VERSION 5.7 ;
BUSBITCHARS "[]" ;
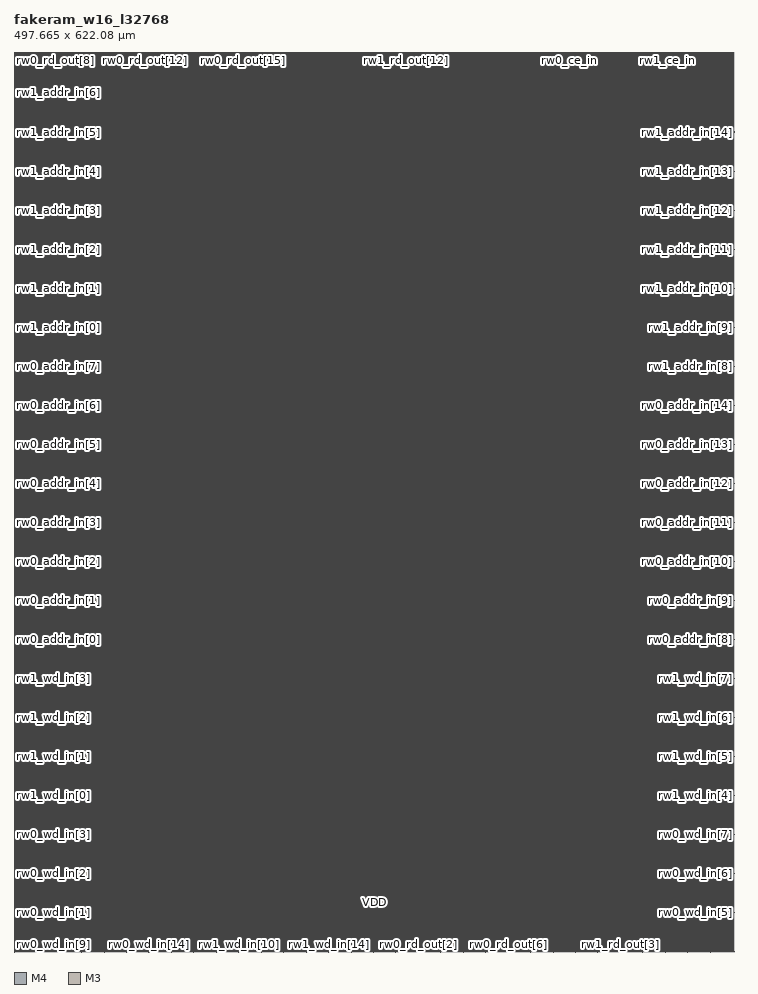
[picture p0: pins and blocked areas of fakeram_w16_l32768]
MACRO fakeram_w16_l32768
  FOREIGN fakeram_w16_l32768 0 0 ;
  SYMMETRY X Y R90 ;
  SIZE 497.665 BY 622.080 ;
  CLASS BLOCK ;
  PIN rw0_wd_in[0]
    DIRECTION INPUT ;
    USE SIGNAL ;
    SHAPE ABUTMENT ;
    PORT
      LAYER M4 ;
      RECT 0.000 0.276 0.072 0.300 ;
    END
  END rw0_wd_in[0]
  PIN rw0_wd_in[1]
    DIRECTION INPUT ;
    USE SIGNAL ;
    SHAPE ABUTMENT ;
    PORT
      LAYER M4 ;
      RECT 0.000 27.252 0.072 27.276 ;
    END
  END rw0_wd_in[1]
  PIN rw0_wd_in[2]
    DIRECTION INPUT ;
    USE SIGNAL ;
    SHAPE ABUTMENT ;
    PORT
      LAYER M4 ;
      RECT 0.000 54.228 0.072 54.252 ;
    END
  END rw0_wd_in[2]
  PIN rw0_wd_in[3]
    DIRECTION INPUT ;
    USE SIGNAL ;
    SHAPE ABUTMENT ;
    PORT
      LAYER M4 ;
      RECT 0.000 81.204 0.072 81.228 ;
    END
  END rw0_wd_in[3]
  PIN rw0_wd_in[4]
    DIRECTION INPUT ;
    USE SIGNAL ;
    SHAPE ABUTMENT ;
    PORT
      LAYER M4 ;
      RECT 497.593 0.276 497.665 0.300 ;
    END
  END rw0_wd_in[4]
  PIN rw0_wd_in[5]
    DIRECTION INPUT ;
    USE SIGNAL ;
    SHAPE ABUTMENT ;
    PORT
      LAYER M4 ;
      RECT 497.593 27.252 497.665 27.276 ;
    END
  END rw0_wd_in[5]
  PIN rw0_wd_in[6]
    DIRECTION INPUT ;
    USE SIGNAL ;
    SHAPE ABUTMENT ;
    PORT
      LAYER M4 ;
      RECT 497.593 54.228 497.665 54.252 ;
    END
  END rw0_wd_in[6]
  PIN rw0_wd_in[7]
    DIRECTION INPUT ;
    USE SIGNAL ;
    SHAPE ABUTMENT ;
    PORT
      LAYER M4 ;
      RECT 497.593 81.204 497.665 81.228 ;
    END
  END rw0_wd_in[7]
  PIN rw0_wd_in[8]
    DIRECTION INPUT ;
    USE SIGNAL ;
    SHAPE ABUTMENT ;
    PORT
      LAYER M3 ;
      RECT 0.207 0.000 0.225 0.054 ;
    END
  END rw0_wd_in[8]
  PIN rw0_wd_in[9]
    DIRECTION INPUT ;
    USE SIGNAL ;
    SHAPE ABUTMENT ;
    PORT
      LAYER M3 ;
      RECT 15.723 0.000 15.741 0.054 ;
    END
  END rw0_wd_in[9]
  PIN rw0_wd_in[10]
    DIRECTION INPUT ;
    USE SIGNAL ;
    SHAPE ABUTMENT ;
    PORT
      LAYER M3 ;
      RECT 31.239 0.000 31.257 0.054 ;
    END
  END rw0_wd_in[10]
  PIN rw0_wd_in[11]
    DIRECTION INPUT ;
    USE SIGNAL ;
    SHAPE ABUTMENT ;
    PORT
      LAYER M3 ;
      RECT 46.755 0.000 46.773 0.054 ;
    END
  END rw0_wd_in[11]
  PIN rw0_wd_in[12]
    DIRECTION INPUT ;
    USE SIGNAL ;
    SHAPE ABUTMENT ;
    PORT
      LAYER M3 ;
      RECT 62.271 0.000 62.289 0.054 ;
    END
  END rw0_wd_in[12]
  PIN rw0_wd_in[13]
    DIRECTION INPUT ;
    USE SIGNAL ;
    SHAPE ABUTMENT ;
    PORT
      LAYER M3 ;
      RECT 77.787 0.000 77.805 0.054 ;
    END
  END rw0_wd_in[13]
  PIN rw0_wd_in[14]
    DIRECTION INPUT ;
    USE SIGNAL ;
    SHAPE ABUTMENT ;
    PORT
      LAYER M3 ;
      RECT 93.303 0.000 93.321 0.054 ;
    END
  END rw0_wd_in[14]
  PIN rw0_wd_in[15]
    DIRECTION INPUT ;
    USE SIGNAL ;
    SHAPE ABUTMENT ;
    PORT
      LAYER M3 ;
      RECT 108.819 0.000 108.837 0.054 ;
    END
  END rw0_wd_in[15]
  PIN rw1_wd_in[0]
    DIRECTION INPUT ;
    USE SIGNAL ;
    SHAPE ABUTMENT ;
    PORT
      LAYER M4 ;
      RECT 0.000 108.180 0.072 108.204 ;
    END
  END rw1_wd_in[0]
  PIN rw1_wd_in[1]
    DIRECTION INPUT ;
    USE SIGNAL ;
    SHAPE ABUTMENT ;
    PORT
      LAYER M4 ;
      RECT 0.000 135.156 0.072 135.180 ;
    END
  END rw1_wd_in[1]
  PIN rw1_wd_in[2]
    DIRECTION INPUT ;
    USE SIGNAL ;
    SHAPE ABUTMENT ;
    PORT
      LAYER M4 ;
      RECT 0.000 162.132 0.072 162.156 ;
    END
  END rw1_wd_in[2]
  PIN rw1_wd_in[3]
    DIRECTION INPUT ;
    USE SIGNAL ;
    SHAPE ABUTMENT ;
    PORT
      LAYER M4 ;
      RECT 0.000 189.108 0.072 189.132 ;
    END
  END rw1_wd_in[3]
  PIN rw1_wd_in[4]
    DIRECTION INPUT ;
    USE SIGNAL ;
    SHAPE ABUTMENT ;
    PORT
      LAYER M4 ;
      RECT 497.593 108.180 497.665 108.204 ;
    END
  END rw1_wd_in[4]
  PIN rw1_wd_in[5]
    DIRECTION INPUT ;
    USE SIGNAL ;
    SHAPE ABUTMENT ;
    PORT
      LAYER M4 ;
      RECT 497.593 135.156 497.665 135.180 ;
    END
  END rw1_wd_in[5]
  PIN rw1_wd_in[6]
    DIRECTION INPUT ;
    USE SIGNAL ;
    SHAPE ABUTMENT ;
    PORT
      LAYER M4 ;
      RECT 497.593 162.132 497.665 162.156 ;
    END
  END rw1_wd_in[6]
  PIN rw1_wd_in[7]
    DIRECTION INPUT ;
    USE SIGNAL ;
    SHAPE ABUTMENT ;
    PORT
      LAYER M4 ;
      RECT 497.593 189.108 497.665 189.132 ;
    END
  END rw1_wd_in[7]
  PIN rw1_wd_in[8]
    DIRECTION INPUT ;
    USE SIGNAL ;
    SHAPE ABUTMENT ;
    PORT
      LAYER M3 ;
      RECT 124.335 0.000 124.353 0.054 ;
    END
  END rw1_wd_in[8]
  PIN rw1_wd_in[9]
    DIRECTION INPUT ;
    USE SIGNAL ;
    SHAPE ABUTMENT ;
    PORT
      LAYER M3 ;
      RECT 139.851 0.000 139.869 0.054 ;
    END
  END rw1_wd_in[9]
  PIN rw1_wd_in[10]
    DIRECTION INPUT ;
    USE SIGNAL ;
    SHAPE ABUTMENT ;
    PORT
      LAYER M3 ;
      RECT 155.367 0.000 155.385 0.054 ;
    END
  END rw1_wd_in[10]
  PIN rw1_wd_in[11]
    DIRECTION INPUT ;
    USE SIGNAL ;
    SHAPE ABUTMENT ;
    PORT
      LAYER M3 ;
      RECT 170.883 0.000 170.901 0.054 ;
    END
  END rw1_wd_in[11]
  PIN rw1_wd_in[12]
    DIRECTION INPUT ;
    USE SIGNAL ;
    SHAPE ABUTMENT ;
    PORT
      LAYER M3 ;
      RECT 186.399 0.000 186.417 0.054 ;
    END
  END rw1_wd_in[12]
  PIN rw1_wd_in[13]
    DIRECTION INPUT ;
    USE SIGNAL ;
    SHAPE ABUTMENT ;
    PORT
      LAYER M3 ;
      RECT 201.915 0.000 201.933 0.054 ;
    END
  END rw1_wd_in[13]
  PIN rw1_wd_in[14]
    DIRECTION INPUT ;
    USE SIGNAL ;
    SHAPE ABUTMENT ;
    PORT
      LAYER M3 ;
      RECT 217.431 0.000 217.449 0.054 ;
    END
  END rw1_wd_in[14]
  PIN rw1_wd_in[15]
    DIRECTION INPUT ;
    USE SIGNAL ;
    SHAPE ABUTMENT ;
    PORT
      LAYER M3 ;
      RECT 232.947 0.000 232.965 0.054 ;
    END
  END rw1_wd_in[15]
  PIN rw0_rd_out[0]
    DIRECTION OUTPUT ;
    USE SIGNAL ;
    SHAPE ABUTMENT ;
    PORT
      LAYER M3 ;
      RECT 248.463 0.000 248.481 0.054 ;
    END
  END rw0_rd_out[0]
  PIN rw0_rd_out[1]
    DIRECTION OUTPUT ;
    USE SIGNAL ;
    SHAPE ABUTMENT ;
    PORT
      LAYER M3 ;
      RECT 263.979 0.000 263.997 0.054 ;
    END
  END rw0_rd_out[1]
  PIN rw0_rd_out[2]
    DIRECTION OUTPUT ;
    USE SIGNAL ;
    SHAPE ABUTMENT ;
    PORT
      LAYER M3 ;
      RECT 279.495 0.000 279.513 0.054 ;
    END
  END rw0_rd_out[2]
  PIN rw0_rd_out[3]
    DIRECTION OUTPUT ;
    USE SIGNAL ;
    SHAPE ABUTMENT ;
    PORT
      LAYER M3 ;
      RECT 295.011 0.000 295.029 0.054 ;
    END
  END rw0_rd_out[3]
  PIN rw0_rd_out[4]
    DIRECTION OUTPUT ;
    USE SIGNAL ;
    SHAPE ABUTMENT ;
    PORT
      LAYER M3 ;
      RECT 310.527 0.000 310.545 0.054 ;
    END
  END rw0_rd_out[4]
  PIN rw0_rd_out[5]
    DIRECTION OUTPUT ;
    USE SIGNAL ;
    SHAPE ABUTMENT ;
    PORT
      LAYER M3 ;
      RECT 326.043 0.000 326.061 0.054 ;
    END
  END rw0_rd_out[5]
  PIN rw0_rd_out[6]
    DIRECTION OUTPUT ;
    USE SIGNAL ;
    SHAPE ABUTMENT ;
    PORT
      LAYER M3 ;
      RECT 341.559 0.000 341.577 0.054 ;
    END
  END rw0_rd_out[6]
  PIN rw0_rd_out[7]
    DIRECTION OUTPUT ;
    USE SIGNAL ;
    SHAPE ABUTMENT ;
    PORT
      LAYER M3 ;
      RECT 357.075 0.000 357.093 0.054 ;
    END
  END rw0_rd_out[7]
  PIN rw0_rd_out[8]
    DIRECTION OUTPUT ;
    USE SIGNAL ;
    SHAPE ABUTMENT ;
    PORT
      LAYER M3 ;
      RECT 0.207 622.026 0.225 622.080 ;
    END
  END rw0_rd_out[8]
  PIN rw0_rd_out[9]
    DIRECTION OUTPUT ;
    USE SIGNAL ;
    SHAPE ABUTMENT ;
    PORT
      LAYER M3 ;
      RECT 22.779 622.026 22.797 622.080 ;
    END
  END rw0_rd_out[9]
  PIN rw0_rd_out[10]
    DIRECTION OUTPUT ;
    USE SIGNAL ;
    SHAPE ABUTMENT ;
    PORT
      LAYER M3 ;
      RECT 45.351 622.026 45.369 622.080 ;
    END
  END rw0_rd_out[10]
  PIN rw0_rd_out[11]
    DIRECTION OUTPUT ;
    USE SIGNAL ;
    SHAPE ABUTMENT ;
    PORT
      LAYER M3 ;
      RECT 67.923 622.026 67.941 622.080 ;
    END
  END rw0_rd_out[11]
  PIN rw0_rd_out[12]
    DIRECTION OUTPUT ;
    USE SIGNAL ;
    SHAPE ABUTMENT ;
    PORT
      LAYER M3 ;
      RECT 90.495 622.026 90.513 622.080 ;
    END
  END rw0_rd_out[12]
  PIN rw0_rd_out[13]
    DIRECTION OUTPUT ;
    USE SIGNAL ;
    SHAPE ABUTMENT ;
    PORT
      LAYER M3 ;
      RECT 113.067 622.026 113.085 622.080 ;
    END
  END rw0_rd_out[13]
  PIN rw0_rd_out[14]
    DIRECTION OUTPUT ;
    USE SIGNAL ;
    SHAPE ABUTMENT ;
    PORT
      LAYER M3 ;
      RECT 135.639 622.026 135.657 622.080 ;
    END
  END rw0_rd_out[14]
  PIN rw0_rd_out[15]
    DIRECTION OUTPUT ;
    USE SIGNAL ;
    SHAPE ABUTMENT ;
    PORT
      LAYER M3 ;
      RECT 158.211 622.026 158.229 622.080 ;
    END
  END rw0_rd_out[15]
  PIN rw1_rd_out[0]
    DIRECTION OUTPUT ;
    USE SIGNAL ;
    SHAPE ABUTMENT ;
    PORT
      LAYER M3 ;
      RECT 372.591 0.000 372.609 0.054 ;
    END
  END rw1_rd_out[0]
  PIN rw1_rd_out[1]
    DIRECTION OUTPUT ;
    USE SIGNAL ;
    SHAPE ABUTMENT ;
    PORT
      LAYER M3 ;
      RECT 388.107 0.000 388.125 0.054 ;
    END
  END rw1_rd_out[1]
  PIN rw1_rd_out[2]
    DIRECTION OUTPUT ;
    USE SIGNAL ;
    SHAPE ABUTMENT ;
    PORT
      LAYER M3 ;
      RECT 403.623 0.000 403.641 0.054 ;
    END
  END rw1_rd_out[2]
  PIN rw1_rd_out[3]
    DIRECTION OUTPUT ;
    USE SIGNAL ;
    SHAPE ABUTMENT ;
    PORT
      LAYER M3 ;
      RECT 419.139 0.000 419.157 0.054 ;
    END
  END rw1_rd_out[3]
  PIN rw1_rd_out[4]
    DIRECTION OUTPUT ;
    USE SIGNAL ;
    SHAPE ABUTMENT ;
    PORT
      LAYER M3 ;
      RECT 434.655 0.000 434.673 0.054 ;
    END
  END rw1_rd_out[4]
  PIN rw1_rd_out[5]
    DIRECTION OUTPUT ;
    USE SIGNAL ;
    SHAPE ABUTMENT ;
    PORT
      LAYER M3 ;
      RECT 450.171 0.000 450.189 0.054 ;
    END
  END rw1_rd_out[5]
  PIN rw1_rd_out[6]
    DIRECTION OUTPUT ;
    USE SIGNAL ;
    SHAPE ABUTMENT ;
    PORT
      LAYER M3 ;
      RECT 465.687 0.000 465.705 0.054 ;
    END
  END rw1_rd_out[6]
  PIN rw1_rd_out[7]
    DIRECTION OUTPUT ;
    USE SIGNAL ;
    SHAPE ABUTMENT ;
    PORT
      LAYER M3 ;
      RECT 481.203 0.000 481.221 0.054 ;
    END
  END rw1_rd_out[7]
  PIN rw1_rd_out[8]
    DIRECTION OUTPUT ;
    USE SIGNAL ;
    SHAPE ABUTMENT ;
    PORT
      LAYER M3 ;
      RECT 180.783 622.026 180.801 622.080 ;
    END
  END rw1_rd_out[8]
  PIN rw1_rd_out[9]
    DIRECTION OUTPUT ;
    USE SIGNAL ;
    SHAPE ABUTMENT ;
    PORT
      LAYER M3 ;
      RECT 203.355 622.026 203.373 622.080 ;
    END
  END rw1_rd_out[9]
  PIN rw1_rd_out[10]
    DIRECTION OUTPUT ;
    USE SIGNAL ;
    SHAPE ABUTMENT ;
    PORT
      LAYER M3 ;
      RECT 225.927 622.026 225.945 622.080 ;
    END
  END rw1_rd_out[10]
  PIN rw1_rd_out[11]
    DIRECTION OUTPUT ;
    USE SIGNAL ;
    SHAPE ABUTMENT ;
    PORT
      LAYER M3 ;
      RECT 248.499 622.026 248.517 622.080 ;
    END
  END rw1_rd_out[11]
  PIN rw1_rd_out[12]
    DIRECTION OUTPUT ;
    USE SIGNAL ;
    SHAPE ABUTMENT ;
    PORT
      LAYER M3 ;
      RECT 271.071 622.026 271.089 622.080 ;
    END
  END rw1_rd_out[12]
  PIN rw1_rd_out[13]
    DIRECTION OUTPUT ;
    USE SIGNAL ;
    SHAPE ABUTMENT ;
    PORT
      LAYER M3 ;
      RECT 293.643 622.026 293.661 622.080 ;
    END
  END rw1_rd_out[13]
  PIN rw1_rd_out[14]
    DIRECTION OUTPUT ;
    USE SIGNAL ;
    SHAPE ABUTMENT ;
    PORT
      LAYER M3 ;
      RECT 316.215 622.026 316.233 622.080 ;
    END
  END rw1_rd_out[14]
  PIN rw1_rd_out[15]
    DIRECTION OUTPUT ;
    USE SIGNAL ;
    SHAPE ABUTMENT ;
    PORT
      LAYER M3 ;
      RECT 338.787 622.026 338.805 622.080 ;
    END
  END rw1_rd_out[15]
  PIN rw0_addr_in[0]
    DIRECTION INPUT ;
    USE SIGNAL ;
    SHAPE ABUTMENT ;
    PORT
      LAYER M4 ;
      RECT 0.000 216.084 0.072 216.108 ;
    END
  END rw0_addr_in[0]
  PIN rw0_addr_in[1]
    DIRECTION INPUT ;
    USE SIGNAL ;
    SHAPE ABUTMENT ;
    PORT
      LAYER M4 ;
      RECT 0.000 243.060 0.072 243.084 ;
    END
  END rw0_addr_in[1]
  PIN rw0_addr_in[2]
    DIRECTION INPUT ;
    USE SIGNAL ;
    SHAPE ABUTMENT ;
    PORT
      LAYER M4 ;
      RECT 0.000 270.036 0.072 270.060 ;
    END
  END rw0_addr_in[2]
  PIN rw0_addr_in[3]
    DIRECTION INPUT ;
    USE SIGNAL ;
    SHAPE ABUTMENT ;
    PORT
      LAYER M4 ;
      RECT 0.000 297.012 0.072 297.036 ;
    END
  END rw0_addr_in[3]
  PIN rw0_addr_in[4]
    DIRECTION INPUT ;
    USE SIGNAL ;
    SHAPE ABUTMENT ;
    PORT
      LAYER M4 ;
      RECT 0.000 323.988 0.072 324.012 ;
    END
  END rw0_addr_in[4]
  PIN rw0_addr_in[5]
    DIRECTION INPUT ;
    USE SIGNAL ;
    SHAPE ABUTMENT ;
    PORT
      LAYER M4 ;
      RECT 0.000 350.964 0.072 350.988 ;
    END
  END rw0_addr_in[5]
  PIN rw0_addr_in[6]
    DIRECTION INPUT ;
    USE SIGNAL ;
    SHAPE ABUTMENT ;
    PORT
      LAYER M4 ;
      RECT 0.000 377.940 0.072 377.964 ;
    END
  END rw0_addr_in[6]
  PIN rw0_addr_in[7]
    DIRECTION INPUT ;
    USE SIGNAL ;
    SHAPE ABUTMENT ;
    PORT
      LAYER M4 ;
      RECT 0.000 404.916 0.072 404.940 ;
    END
  END rw0_addr_in[7]
  PIN rw0_addr_in[8]
    DIRECTION INPUT ;
    USE SIGNAL ;
    SHAPE ABUTMENT ;
    PORT
      LAYER M4 ;
      RECT 497.593 216.084 497.665 216.108 ;
    END
  END rw0_addr_in[8]
  PIN rw0_addr_in[9]
    DIRECTION INPUT ;
    USE SIGNAL ;
    SHAPE ABUTMENT ;
    PORT
      LAYER M4 ;
      RECT 497.593 243.060 497.665 243.084 ;
    END
  END rw0_addr_in[9]
  PIN rw0_addr_in[10]
    DIRECTION INPUT ;
    USE SIGNAL ;
    SHAPE ABUTMENT ;
    PORT
      LAYER M4 ;
      RECT 497.593 270.036 497.665 270.060 ;
    END
  END rw0_addr_in[10]
  PIN rw0_addr_in[11]
    DIRECTION INPUT ;
    USE SIGNAL ;
    SHAPE ABUTMENT ;
    PORT
      LAYER M4 ;
      RECT 497.593 297.012 497.665 297.036 ;
    END
  END rw0_addr_in[11]
  PIN rw0_addr_in[12]
    DIRECTION INPUT ;
    USE SIGNAL ;
    SHAPE ABUTMENT ;
    PORT
      LAYER M4 ;
      RECT 497.593 323.988 497.665 324.012 ;
    END
  END rw0_addr_in[12]
  PIN rw0_addr_in[13]
    DIRECTION INPUT ;
    USE SIGNAL ;
    SHAPE ABUTMENT ;
    PORT
      LAYER M4 ;
      RECT 497.593 350.964 497.665 350.988 ;
    END
  END rw0_addr_in[13]
  PIN rw0_addr_in[14]
    DIRECTION INPUT ;
    USE SIGNAL ;
    SHAPE ABUTMENT ;
    PORT
      LAYER M4 ;
      RECT 497.593 377.940 497.665 377.964 ;
    END
  END rw0_addr_in[14]
  PIN rw1_addr_in[0]
    DIRECTION INPUT ;
    USE SIGNAL ;
    SHAPE ABUTMENT ;
    PORT
      LAYER M4 ;
      RECT 0.000 431.892 0.072 431.916 ;
    END
  END rw1_addr_in[0]
  PIN rw1_addr_in[1]
    DIRECTION INPUT ;
    USE SIGNAL ;
    SHAPE ABUTMENT ;
    PORT
      LAYER M4 ;
      RECT 0.000 458.868 0.072 458.892 ;
    END
  END rw1_addr_in[1]
  PIN rw1_addr_in[2]
    DIRECTION INPUT ;
    USE SIGNAL ;
    SHAPE ABUTMENT ;
    PORT
      LAYER M4 ;
      RECT 0.000 485.844 0.072 485.868 ;
    END
  END rw1_addr_in[2]
  PIN rw1_addr_in[3]
    DIRECTION INPUT ;
    USE SIGNAL ;
    SHAPE ABUTMENT ;
    PORT
      LAYER M4 ;
      RECT 0.000 512.820 0.072 512.844 ;
    END
  END rw1_addr_in[3]
  PIN rw1_addr_in[4]
    DIRECTION INPUT ;
    USE SIGNAL ;
    SHAPE ABUTMENT ;
    PORT
      LAYER M4 ;
      RECT 0.000 539.796 0.072 539.820 ;
    END
  END rw1_addr_in[4]
  PIN rw1_addr_in[5]
    DIRECTION INPUT ;
    USE SIGNAL ;
    SHAPE ABUTMENT ;
    PORT
      LAYER M4 ;
      RECT 0.000 566.772 0.072 566.796 ;
    END
  END rw1_addr_in[5]
  PIN rw1_addr_in[6]
    DIRECTION INPUT ;
    USE SIGNAL ;
    SHAPE ABUTMENT ;
    PORT
      LAYER M4 ;
      RECT 0.000 593.748 0.072 593.772 ;
    END
  END rw1_addr_in[6]
  PIN rw1_addr_in[7]
    DIRECTION INPUT ;
    USE SIGNAL ;
    SHAPE ABUTMENT ;
    PORT
      LAYER M4 ;
      RECT 0.000 620.724 0.072 620.748 ;
    END
  END rw1_addr_in[7]
  PIN rw1_addr_in[8]
    DIRECTION INPUT ;
    USE SIGNAL ;
    SHAPE ABUTMENT ;
    PORT
      LAYER M4 ;
      RECT 497.593 404.916 497.665 404.940 ;
    END
  END rw1_addr_in[8]
  PIN rw1_addr_in[9]
    DIRECTION INPUT ;
    USE SIGNAL ;
    SHAPE ABUTMENT ;
    PORT
      LAYER M4 ;
      RECT 497.593 431.892 497.665 431.916 ;
    END
  END rw1_addr_in[9]
  PIN rw1_addr_in[10]
    DIRECTION INPUT ;
    USE SIGNAL ;
    SHAPE ABUTMENT ;
    PORT
      LAYER M4 ;
      RECT 497.593 458.868 497.665 458.892 ;
    END
  END rw1_addr_in[10]
  PIN rw1_addr_in[11]
    DIRECTION INPUT ;
    USE SIGNAL ;
    SHAPE ABUTMENT ;
    PORT
      LAYER M4 ;
      RECT 497.593 485.844 497.665 485.868 ;
    END
  END rw1_addr_in[11]
  PIN rw1_addr_in[12]
    DIRECTION INPUT ;
    USE SIGNAL ;
    SHAPE ABUTMENT ;
    PORT
      LAYER M4 ;
      RECT 497.593 512.820 497.665 512.844 ;
    END
  END rw1_addr_in[12]
  PIN rw1_addr_in[13]
    DIRECTION INPUT ;
    USE SIGNAL ;
    SHAPE ABUTMENT ;
    PORT
      LAYER M4 ;
      RECT 497.593 539.796 497.665 539.820 ;
    END
  END rw1_addr_in[13]
  PIN rw1_addr_in[14]
    DIRECTION INPUT ;
    USE SIGNAL ;
    SHAPE ABUTMENT ;
    PORT
      LAYER M4 ;
      RECT 497.593 566.772 497.665 566.796 ;
    END
  END rw1_addr_in[14]
  PIN rw0_we_in
    DIRECTION INPUT ;
    USE SIGNAL ;
    SHAPE ABUTMENT ;
    PORT
      LAYER M3 ;
      RECT 361.359 622.026 361.377 622.080 ;
    END
  END rw0_we_in
  PIN rw0_ce_in
    DIRECTION INPUT ;
    USE SIGNAL ;
    SHAPE ABUTMENT ;
    PORT
      LAYER M3 ;
      RECT 383.931 622.026 383.949 622.080 ;
    END
  END rw0_ce_in
  PIN rw0_clk
    DIRECTION INPUT ;
    USE SIGNAL ;
    SHAPE ABUTMENT ;
    PORT
      LAYER M3 ;
      RECT 406.503 622.026 406.521 622.080 ;
    END
  END rw0_clk
  PIN rw1_we_in
    DIRECTION INPUT ;
    USE SIGNAL ;
    SHAPE ABUTMENT ;
    PORT
      LAYER M3 ;
      RECT 429.075 622.026 429.093 622.080 ;
    END
  END rw1_we_in
  PIN rw1_ce_in
    DIRECTION INPUT ;
    USE SIGNAL ;
    SHAPE ABUTMENT ;
    PORT
      LAYER M3 ;
      RECT 451.647 622.026 451.665 622.080 ;
    END
  END rw1_ce_in
  PIN rw1_clk
    DIRECTION INPUT ;
    USE SIGNAL ;
    SHAPE ABUTMENT ;
    PORT
      LAYER M3 ;
      RECT 474.219 622.026 474.237 622.080 ;
    END
  END rw1_clk
  PIN VSS
    DIRECTION INOUT ;
    USE GROUND ;
    PORT
      LAYER M4 ;
      RECT 0.216 0.240 497.449 0.336 ;
      RECT 0.216 1.008 497.449 1.104 ;
      RECT 0.216 1.776 497.449 1.872 ;
      RECT 0.216 2.544 497.449 2.640 ;
      RECT 0.216 3.312 497.449 3.408 ;
      RECT 0.216 4.080 497.449 4.176 ;
      RECT 0.216 4.848 497.449 4.944 ;
      RECT 0.216 5.616 497.449 5.712 ;
      RECT 0.216 6.384 497.449 6.480 ;
      RECT 0.216 7.152 497.449 7.248 ;
      RECT 0.216 7.920 497.449 8.016 ;
      RECT 0.216 8.688 497.449 8.784 ;
      RECT 0.216 9.456 497.449 9.552 ;
      RECT 0.216 10.224 497.449 10.320 ;
      RECT 0.216 10.992 497.449 11.088 ;
      RECT 0.216 11.760 497.449 11.856 ;
      RECT 0.216 12.528 497.449 12.624 ;
      RECT 0.216 13.296 497.449 13.392 ;
      RECT 0.216 14.064 497.449 14.160 ;
      RECT 0.216 14.832 497.449 14.928 ;
      RECT 0.216 15.600 497.449 15.696 ;
      RECT 0.216 16.368 497.449 16.464 ;
      RECT 0.216 17.136 497.449 17.232 ;
      RECT 0.216 17.904 497.449 18.000 ;
      RECT 0.216 18.672 497.449 18.768 ;
      RECT 0.216 19.440 497.449 19.536 ;
      RECT 0.216 20.208 497.449 20.304 ;
      RECT 0.216 20.976 497.449 21.072 ;
      RECT 0.216 21.744 497.449 21.840 ;
      RECT 0.216 22.512 497.449 22.608 ;
      RECT 0.216 23.280 497.449 23.376 ;
      RECT 0.216 24.048 497.449 24.144 ;
      RECT 0.216 24.816 497.449 24.912 ;
      RECT 0.216 25.584 497.449 25.680 ;
      RECT 0.216 26.352 497.449 26.448 ;
      RECT 0.216 27.120 497.449 27.216 ;
      RECT 0.216 27.888 497.449 27.984 ;
      RECT 0.216 28.656 497.449 28.752 ;
      RECT 0.216 29.424 497.449 29.520 ;
      RECT 0.216 30.192 497.449 30.288 ;
      RECT 0.216 30.960 497.449 31.056 ;
      RECT 0.216 31.728 497.449 31.824 ;
      RECT 0.216 32.496 497.449 32.592 ;
      RECT 0.216 33.264 497.449 33.360 ;
      RECT 0.216 34.032 497.449 34.128 ;
      RECT 0.216 34.800 497.449 34.896 ;
      RECT 0.216 35.568 497.449 35.664 ;
      RECT 0.216 36.336 497.449 36.432 ;
      RECT 0.216 37.104 497.449 37.200 ;
      RECT 0.216 37.872 497.449 37.968 ;
      RECT 0.216 38.640 497.449 38.736 ;
      RECT 0.216 39.408 497.449 39.504 ;
      RECT 0.216 40.176 497.449 40.272 ;
      RECT 0.216 40.944 497.449 41.040 ;
      RECT 0.216 41.712 497.449 41.808 ;
      RECT 0.216 42.480 497.449 42.576 ;
      RECT 0.216 43.248 497.449 43.344 ;
      RECT 0.216 44.016 497.449 44.112 ;
      RECT 0.216 44.784 497.449 44.880 ;
      RECT 0.216 45.552 497.449 45.648 ;
      RECT 0.216 46.320 497.449 46.416 ;
      RECT 0.216 47.088 497.449 47.184 ;
      RECT 0.216 47.856 497.449 47.952 ;
      RECT 0.216 48.624 497.449 48.720 ;
      RECT 0.216 49.392 497.449 49.488 ;
      RECT 0.216 50.160 497.449 50.256 ;
      RECT 0.216 50.928 497.449 51.024 ;
      RECT 0.216 51.696 497.449 51.792 ;
      RECT 0.216 52.464 497.449 52.560 ;
      RECT 0.216 53.232 497.449 53.328 ;
      RECT 0.216 54.000 497.449 54.096 ;
      RECT 0.216 54.768 497.449 54.864 ;
      RECT 0.216 55.536 497.449 55.632 ;
      RECT 0.216 56.304 497.449 56.400 ;
      RECT 0.216 57.072 497.449 57.168 ;
      RECT 0.216 57.840 497.449 57.936 ;
      RECT 0.216 58.608 497.449 58.704 ;
      RECT 0.216 59.376 497.449 59.472 ;
      RECT 0.216 60.144 497.449 60.240 ;
      RECT 0.216 60.912 497.449 61.008 ;
      RECT 0.216 61.680 497.449 61.776 ;
      RECT 0.216 62.448 497.449 62.544 ;
      RECT 0.216 63.216 497.449 63.312 ;
      RECT 0.216 63.984 497.449 64.080 ;
      RECT 0.216 64.752 497.449 64.848 ;
      RECT 0.216 65.520 497.449 65.616 ;
      RECT 0.216 66.288 497.449 66.384 ;
      RECT 0.216 67.056 497.449 67.152 ;
      RECT 0.216 67.824 497.449 67.920 ;
      RECT 0.216 68.592 497.449 68.688 ;
      RECT 0.216 69.360 497.449 69.456 ;
      RECT 0.216 70.128 497.449 70.224 ;
      RECT 0.216 70.896 497.449 70.992 ;
      RECT 0.216 71.664 497.449 71.760 ;
      RECT 0.216 72.432 497.449 72.528 ;
      RECT 0.216 73.200 497.449 73.296 ;
      RECT 0.216 73.968 497.449 74.064 ;
      RECT 0.216 74.736 497.449 74.832 ;
      RECT 0.216 75.504 497.449 75.600 ;
      RECT 0.216 76.272 497.449 76.368 ;
      RECT 0.216 77.040 497.449 77.136 ;
      RECT 0.216 77.808 497.449 77.904 ;
      RECT 0.216 78.576 497.449 78.672 ;
      RECT 0.216 79.344 497.449 79.440 ;
      RECT 0.216 80.112 497.449 80.208 ;
      RECT 0.216 80.880 497.449 80.976 ;
      RECT 0.216 81.648 497.449 81.744 ;
      RECT 0.216 82.416 497.449 82.512 ;
      RECT 0.216 83.184 497.449 83.280 ;
      RECT 0.216 83.952 497.449 84.048 ;
      RECT 0.216 84.720 497.449 84.816 ;
      RECT 0.216 85.488 497.449 85.584 ;
      RECT 0.216 86.256 497.449 86.352 ;
      RECT 0.216 87.024 497.449 87.120 ;
      RECT 0.216 87.792 497.449 87.888 ;
      RECT 0.216 88.560 497.449 88.656 ;
      RECT 0.216 89.328 497.449 89.424 ;
      RECT 0.216 90.096 497.449 90.192 ;
      RECT 0.216 90.864 497.449 90.960 ;
      RECT 0.216 91.632 497.449 91.728 ;
      RECT 0.216 92.400 497.449 92.496 ;
      RECT 0.216 93.168 497.449 93.264 ;
      RECT 0.216 93.936 497.449 94.032 ;
      RECT 0.216 94.704 497.449 94.800 ;
      RECT 0.216 95.472 497.449 95.568 ;
      RECT 0.216 96.240 497.449 96.336 ;
      RECT 0.216 97.008 497.449 97.104 ;
      RECT 0.216 97.776 497.449 97.872 ;
      RECT 0.216 98.544 497.449 98.640 ;
      RECT 0.216 99.312 497.449 99.408 ;
      RECT 0.216 100.080 497.449 100.176 ;
      RECT 0.216 100.848 497.449 100.944 ;
      RECT 0.216 101.616 497.449 101.712 ;
      RECT 0.216 102.384 497.449 102.480 ;
      RECT 0.216 103.152 497.449 103.248 ;
      RECT 0.216 103.920 497.449 104.016 ;
      RECT 0.216 104.688 497.449 104.784 ;
      RECT 0.216 105.456 497.449 105.552 ;
      RECT 0.216 106.224 497.449 106.320 ;
      RECT 0.216 106.992 497.449 107.088 ;
      RECT 0.216 107.760 497.449 107.856 ;
      RECT 0.216 108.528 497.449 108.624 ;
      RECT 0.216 109.296 497.449 109.392 ;
      RECT 0.216 110.064 497.449 110.160 ;
      RECT 0.216 110.832 497.449 110.928 ;
      RECT 0.216 111.600 497.449 111.696 ;
      RECT 0.216 112.368 497.449 112.464 ;
      RECT 0.216 113.136 497.449 113.232 ;
      RECT 0.216 113.904 497.449 114.000 ;
      RECT 0.216 114.672 497.449 114.768 ;
      RECT 0.216 115.440 497.449 115.536 ;
      RECT 0.216 116.208 497.449 116.304 ;
      RECT 0.216 116.976 497.449 117.072 ;
      RECT 0.216 117.744 497.449 117.840 ;
      RECT 0.216 118.512 497.449 118.608 ;
      RECT 0.216 119.280 497.449 119.376 ;
      RECT 0.216 120.048 497.449 120.144 ;
      RECT 0.216 120.816 497.449 120.912 ;
      RECT 0.216 121.584 497.449 121.680 ;
      RECT 0.216 122.352 497.449 122.448 ;
      RECT 0.216 123.120 497.449 123.216 ;
      RECT 0.216 123.888 497.449 123.984 ;
      RECT 0.216 124.656 497.449 124.752 ;
      RECT 0.216 125.424 497.449 125.520 ;
      RECT 0.216 126.192 497.449 126.288 ;
      RECT 0.216 126.960 497.449 127.056 ;
      RECT 0.216 127.728 497.449 127.824 ;
      RECT 0.216 128.496 497.449 128.592 ;
      RECT 0.216 129.264 497.449 129.360 ;
      RECT 0.216 130.032 497.449 130.128 ;
      RECT 0.216 130.800 497.449 130.896 ;
      RECT 0.216 131.568 497.449 131.664 ;
      RECT 0.216 132.336 497.449 132.432 ;
      RECT 0.216 133.104 497.449 133.200 ;
      RECT 0.216 133.872 497.449 133.968 ;
      RECT 0.216 134.640 497.449 134.736 ;
      RECT 0.216 135.408 497.449 135.504 ;
      RECT 0.216 136.176 497.449 136.272 ;
      RECT 0.216 136.944 497.449 137.040 ;
      RECT 0.216 137.712 497.449 137.808 ;
      RECT 0.216 138.480 497.449 138.576 ;
      RECT 0.216 139.248 497.449 139.344 ;
      RECT 0.216 140.016 497.449 140.112 ;
      RECT 0.216 140.784 497.449 140.880 ;
      RECT 0.216 141.552 497.449 141.648 ;
      RECT 0.216 142.320 497.449 142.416 ;
      RECT 0.216 143.088 497.449 143.184 ;
      RECT 0.216 143.856 497.449 143.952 ;
      RECT 0.216 144.624 497.449 144.720 ;
      RECT 0.216 145.392 497.449 145.488 ;
      RECT 0.216 146.160 497.449 146.256 ;
      RECT 0.216 146.928 497.449 147.024 ;
      RECT 0.216 147.696 497.449 147.792 ;
      RECT 0.216 148.464 497.449 148.560 ;
      RECT 0.216 149.232 497.449 149.328 ;
      RECT 0.216 150.000 497.449 150.096 ;
      RECT 0.216 150.768 497.449 150.864 ;
      RECT 0.216 151.536 497.449 151.632 ;
      RECT 0.216 152.304 497.449 152.400 ;
      RECT 0.216 153.072 497.449 153.168 ;
      RECT 0.216 153.840 497.449 153.936 ;
      RECT 0.216 154.608 497.449 154.704 ;
      RECT 0.216 155.376 497.449 155.472 ;
      RECT 0.216 156.144 497.449 156.240 ;
      RECT 0.216 156.912 497.449 157.008 ;
      RECT 0.216 157.680 497.449 157.776 ;
      RECT 0.216 158.448 497.449 158.544 ;
      RECT 0.216 159.216 497.449 159.312 ;
      RECT 0.216 159.984 497.449 160.080 ;
      RECT 0.216 160.752 497.449 160.848 ;
      RECT 0.216 161.520 497.449 161.616 ;
      RECT 0.216 162.288 497.449 162.384 ;
      RECT 0.216 163.056 497.449 163.152 ;
      RECT 0.216 163.824 497.449 163.920 ;
      RECT 0.216 164.592 497.449 164.688 ;
      RECT 0.216 165.360 497.449 165.456 ;
      RECT 0.216 166.128 497.449 166.224 ;
      RECT 0.216 166.896 497.449 166.992 ;
      RECT 0.216 167.664 497.449 167.760 ;
      RECT 0.216 168.432 497.449 168.528 ;
      RECT 0.216 169.200 497.449 169.296 ;
      RECT 0.216 169.968 497.449 170.064 ;
      RECT 0.216 170.736 497.449 170.832 ;
      RECT 0.216 171.504 497.449 171.600 ;
      RECT 0.216 172.272 497.449 172.368 ;
      RECT 0.216 173.040 497.449 173.136 ;
      RECT 0.216 173.808 497.449 173.904 ;
      RECT 0.216 174.576 497.449 174.672 ;
      RECT 0.216 175.344 497.449 175.440 ;
      RECT 0.216 176.112 497.449 176.208 ;
      RECT 0.216 176.880 497.449 176.976 ;
      RECT 0.216 177.648 497.449 177.744 ;
      RECT 0.216 178.416 497.449 178.512 ;
      RECT 0.216 179.184 497.449 179.280 ;
      RECT 0.216 179.952 497.449 180.048 ;
      RECT 0.216 180.720 497.449 180.816 ;
      RECT 0.216 181.488 497.449 181.584 ;
      RECT 0.216 182.256 497.449 182.352 ;
      RECT 0.216 183.024 497.449 183.120 ;
      RECT 0.216 183.792 497.449 183.888 ;
      RECT 0.216 184.560 497.449 184.656 ;
      RECT 0.216 185.328 497.449 185.424 ;
      RECT 0.216 186.096 497.449 186.192 ;
      RECT 0.216 186.864 497.449 186.960 ;
      RECT 0.216 187.632 497.449 187.728 ;
      RECT 0.216 188.400 497.449 188.496 ;
      RECT 0.216 189.168 497.449 189.264 ;
      RECT 0.216 189.936 497.449 190.032 ;
      RECT 0.216 190.704 497.449 190.800 ;
      RECT 0.216 191.472 497.449 191.568 ;
      RECT 0.216 192.240 497.449 192.336 ;
      RECT 0.216 193.008 497.449 193.104 ;
      RECT 0.216 193.776 497.449 193.872 ;
      RECT 0.216 194.544 497.449 194.640 ;
      RECT 0.216 195.312 497.449 195.408 ;
      RECT 0.216 196.080 497.449 196.176 ;
      RECT 0.216 196.848 497.449 196.944 ;
      RECT 0.216 197.616 497.449 197.712 ;
      RECT 0.216 198.384 497.449 198.480 ;
      RECT 0.216 199.152 497.449 199.248 ;
      RECT 0.216 199.920 497.449 200.016 ;
      RECT 0.216 200.688 497.449 200.784 ;
      RECT 0.216 201.456 497.449 201.552 ;
      RECT 0.216 202.224 497.449 202.320 ;
      RECT 0.216 202.992 497.449 203.088 ;
      RECT 0.216 203.760 497.449 203.856 ;
      RECT 0.216 204.528 497.449 204.624 ;
      RECT 0.216 205.296 497.449 205.392 ;
      RECT 0.216 206.064 497.449 206.160 ;
      RECT 0.216 206.832 497.449 206.928 ;
      RECT 0.216 207.600 497.449 207.696 ;
      RECT 0.216 208.368 497.449 208.464 ;
      RECT 0.216 209.136 497.449 209.232 ;
      RECT 0.216 209.904 497.449 210.000 ;
      RECT 0.216 210.672 497.449 210.768 ;
      RECT 0.216 211.440 497.449 211.536 ;
      RECT 0.216 212.208 497.449 212.304 ;
      RECT 0.216 212.976 497.449 213.072 ;
      RECT 0.216 213.744 497.449 213.840 ;
      RECT 0.216 214.512 497.449 214.608 ;
      RECT 0.216 215.280 497.449 215.376 ;
      RECT 0.216 216.048 497.449 216.144 ;
      RECT 0.216 216.816 497.449 216.912 ;
      RECT 0.216 217.584 497.449 217.680 ;
      RECT 0.216 218.352 497.449 218.448 ;
      RECT 0.216 219.120 497.449 219.216 ;
      RECT 0.216 219.888 497.449 219.984 ;
      RECT 0.216 220.656 497.449 220.752 ;
      RECT 0.216 221.424 497.449 221.520 ;
      RECT 0.216 222.192 497.449 222.288 ;
      RECT 0.216 222.960 497.449 223.056 ;
      RECT 0.216 223.728 497.449 223.824 ;
      RECT 0.216 224.496 497.449 224.592 ;
      RECT 0.216 225.264 497.449 225.360 ;
      RECT 0.216 226.032 497.449 226.128 ;
      RECT 0.216 226.800 497.449 226.896 ;
      RECT 0.216 227.568 497.449 227.664 ;
      RECT 0.216 228.336 497.449 228.432 ;
      RECT 0.216 229.104 497.449 229.200 ;
      RECT 0.216 229.872 497.449 229.968 ;
      RECT 0.216 230.640 497.449 230.736 ;
      RECT 0.216 231.408 497.449 231.504 ;
      RECT 0.216 232.176 497.449 232.272 ;
      RECT 0.216 232.944 497.449 233.040 ;
      RECT 0.216 233.712 497.449 233.808 ;
      RECT 0.216 234.480 497.449 234.576 ;
      RECT 0.216 235.248 497.449 235.344 ;
      RECT 0.216 236.016 497.449 236.112 ;
      RECT 0.216 236.784 497.449 236.880 ;
      RECT 0.216 237.552 497.449 237.648 ;
      RECT 0.216 238.320 497.449 238.416 ;
      RECT 0.216 239.088 497.449 239.184 ;
      RECT 0.216 239.856 497.449 239.952 ;
      RECT 0.216 240.624 497.449 240.720 ;
      RECT 0.216 241.392 497.449 241.488 ;
      RECT 0.216 242.160 497.449 242.256 ;
      RECT 0.216 242.928 497.449 243.024 ;
      RECT 0.216 243.696 497.449 243.792 ;
      RECT 0.216 244.464 497.449 244.560 ;
      RECT 0.216 245.232 497.449 245.328 ;
      RECT 0.216 246.000 497.449 246.096 ;
      RECT 0.216 246.768 497.449 246.864 ;
      RECT 0.216 247.536 497.449 247.632 ;
      RECT 0.216 248.304 497.449 248.400 ;
      RECT 0.216 249.072 497.449 249.168 ;
      RECT 0.216 249.840 497.449 249.936 ;
      RECT 0.216 250.608 497.449 250.704 ;
      RECT 0.216 251.376 497.449 251.472 ;
      RECT 0.216 252.144 497.449 252.240 ;
      RECT 0.216 252.912 497.449 253.008 ;
      RECT 0.216 253.680 497.449 253.776 ;
      RECT 0.216 254.448 497.449 254.544 ;
      RECT 0.216 255.216 497.449 255.312 ;
      RECT 0.216 255.984 497.449 256.080 ;
      RECT 0.216 256.752 497.449 256.848 ;
      RECT 0.216 257.520 497.449 257.616 ;
      RECT 0.216 258.288 497.449 258.384 ;
      RECT 0.216 259.056 497.449 259.152 ;
      RECT 0.216 259.824 497.449 259.920 ;
      RECT 0.216 260.592 497.449 260.688 ;
      RECT 0.216 261.360 497.449 261.456 ;
      RECT 0.216 262.128 497.449 262.224 ;
      RECT 0.216 262.896 497.449 262.992 ;
      RECT 0.216 263.664 497.449 263.760 ;
      RECT 0.216 264.432 497.449 264.528 ;
      RECT 0.216 265.200 497.449 265.296 ;
      RECT 0.216 265.968 497.449 266.064 ;
      RECT 0.216 266.736 497.449 266.832 ;
      RECT 0.216 267.504 497.449 267.600 ;
      RECT 0.216 268.272 497.449 268.368 ;
      RECT 0.216 269.040 497.449 269.136 ;
      RECT 0.216 269.808 497.449 269.904 ;
      RECT 0.216 270.576 497.449 270.672 ;
      RECT 0.216 271.344 497.449 271.440 ;
      RECT 0.216 272.112 497.449 272.208 ;
      RECT 0.216 272.880 497.449 272.976 ;
      RECT 0.216 273.648 497.449 273.744 ;
      RECT 0.216 274.416 497.449 274.512 ;
      RECT 0.216 275.184 497.449 275.280 ;
      RECT 0.216 275.952 497.449 276.048 ;
      RECT 0.216 276.720 497.449 276.816 ;
      RECT 0.216 277.488 497.449 277.584 ;
      RECT 0.216 278.256 497.449 278.352 ;
      RECT 0.216 279.024 497.449 279.120 ;
      RECT 0.216 279.792 497.449 279.888 ;
      RECT 0.216 280.560 497.449 280.656 ;
      RECT 0.216 281.328 497.449 281.424 ;
      RECT 0.216 282.096 497.449 282.192 ;
      RECT 0.216 282.864 497.449 282.960 ;
      RECT 0.216 283.632 497.449 283.728 ;
      RECT 0.216 284.400 497.449 284.496 ;
      RECT 0.216 285.168 497.449 285.264 ;
      RECT 0.216 285.936 497.449 286.032 ;
      RECT 0.216 286.704 497.449 286.800 ;
      RECT 0.216 287.472 497.449 287.568 ;
      RECT 0.216 288.240 497.449 288.336 ;
      RECT 0.216 289.008 497.449 289.104 ;
      RECT 0.216 289.776 497.449 289.872 ;
      RECT 0.216 290.544 497.449 290.640 ;
      RECT 0.216 291.312 497.449 291.408 ;
      RECT 0.216 292.080 497.449 292.176 ;
      RECT 0.216 292.848 497.449 292.944 ;
      RECT 0.216 293.616 497.449 293.712 ;
      RECT 0.216 294.384 497.449 294.480 ;
      RECT 0.216 295.152 497.449 295.248 ;
      RECT 0.216 295.920 497.449 296.016 ;
      RECT 0.216 296.688 497.449 296.784 ;
      RECT 0.216 297.456 497.449 297.552 ;
      RECT 0.216 298.224 497.449 298.320 ;
      RECT 0.216 298.992 497.449 299.088 ;
      RECT 0.216 299.760 497.449 299.856 ;
      RECT 0.216 300.528 497.449 300.624 ;
      RECT 0.216 301.296 497.449 301.392 ;
      RECT 0.216 302.064 497.449 302.160 ;
      RECT 0.216 302.832 497.449 302.928 ;
      RECT 0.216 303.600 497.449 303.696 ;
      RECT 0.216 304.368 497.449 304.464 ;
      RECT 0.216 305.136 497.449 305.232 ;
      RECT 0.216 305.904 497.449 306.000 ;
      RECT 0.216 306.672 497.449 306.768 ;
      RECT 0.216 307.440 497.449 307.536 ;
      RECT 0.216 308.208 497.449 308.304 ;
      RECT 0.216 308.976 497.449 309.072 ;
      RECT 0.216 309.744 497.449 309.840 ;
      RECT 0.216 310.512 497.449 310.608 ;
      RECT 0.216 311.280 497.449 311.376 ;
      RECT 0.216 312.048 497.449 312.144 ;
      RECT 0.216 312.816 497.449 312.912 ;
      RECT 0.216 313.584 497.449 313.680 ;
      RECT 0.216 314.352 497.449 314.448 ;
      RECT 0.216 315.120 497.449 315.216 ;
      RECT 0.216 315.888 497.449 315.984 ;
      RECT 0.216 316.656 497.449 316.752 ;
      RECT 0.216 317.424 497.449 317.520 ;
      RECT 0.216 318.192 497.449 318.288 ;
      RECT 0.216 318.960 497.449 319.056 ;
      RECT 0.216 319.728 497.449 319.824 ;
      RECT 0.216 320.496 497.449 320.592 ;
      RECT 0.216 321.264 497.449 321.360 ;
      RECT 0.216 322.032 497.449 322.128 ;
      RECT 0.216 322.800 497.449 322.896 ;
      RECT 0.216 323.568 497.449 323.664 ;
      RECT 0.216 324.336 497.449 324.432 ;
      RECT 0.216 325.104 497.449 325.200 ;
      RECT 0.216 325.872 497.449 325.968 ;
      RECT 0.216 326.640 497.449 326.736 ;
      RECT 0.216 327.408 497.449 327.504 ;
      RECT 0.216 328.176 497.449 328.272 ;
      RECT 0.216 328.944 497.449 329.040 ;
      RECT 0.216 329.712 497.449 329.808 ;
      RECT 0.216 330.480 497.449 330.576 ;
      RECT 0.216 331.248 497.449 331.344 ;
      RECT 0.216 332.016 497.449 332.112 ;
      RECT 0.216 332.784 497.449 332.880 ;
      RECT 0.216 333.552 497.449 333.648 ;
      RECT 0.216 334.320 497.449 334.416 ;
      RECT 0.216 335.088 497.449 335.184 ;
      RECT 0.216 335.856 497.449 335.952 ;
      RECT 0.216 336.624 497.449 336.720 ;
      RECT 0.216 337.392 497.449 337.488 ;
      RECT 0.216 338.160 497.449 338.256 ;
      RECT 0.216 338.928 497.449 339.024 ;
      RECT 0.216 339.696 497.449 339.792 ;
      RECT 0.216 340.464 497.449 340.560 ;
      RECT 0.216 341.232 497.449 341.328 ;
      RECT 0.216 342.000 497.449 342.096 ;
      RECT 0.216 342.768 497.449 342.864 ;
      RECT 0.216 343.536 497.449 343.632 ;
      RECT 0.216 344.304 497.449 344.400 ;
      RECT 0.216 345.072 497.449 345.168 ;
      RECT 0.216 345.840 497.449 345.936 ;
      RECT 0.216 346.608 497.449 346.704 ;
      RECT 0.216 347.376 497.449 347.472 ;
      RECT 0.216 348.144 497.449 348.240 ;
      RECT 0.216 348.912 497.449 349.008 ;
      RECT 0.216 349.680 497.449 349.776 ;
      RECT 0.216 350.448 497.449 350.544 ;
      RECT 0.216 351.216 497.449 351.312 ;
      RECT 0.216 351.984 497.449 352.080 ;
      RECT 0.216 352.752 497.449 352.848 ;
      RECT 0.216 353.520 497.449 353.616 ;
      RECT 0.216 354.288 497.449 354.384 ;
      RECT 0.216 355.056 497.449 355.152 ;
      RECT 0.216 355.824 497.449 355.920 ;
      RECT 0.216 356.592 497.449 356.688 ;
      RECT 0.216 357.360 497.449 357.456 ;
      RECT 0.216 358.128 497.449 358.224 ;
      RECT 0.216 358.896 497.449 358.992 ;
      RECT 0.216 359.664 497.449 359.760 ;
      RECT 0.216 360.432 497.449 360.528 ;
      RECT 0.216 361.200 497.449 361.296 ;
      RECT 0.216 361.968 497.449 362.064 ;
      RECT 0.216 362.736 497.449 362.832 ;
      RECT 0.216 363.504 497.449 363.600 ;
      RECT 0.216 364.272 497.449 364.368 ;
      RECT 0.216 365.040 497.449 365.136 ;
      RECT 0.216 365.808 497.449 365.904 ;
      RECT 0.216 366.576 497.449 366.672 ;
      RECT 0.216 367.344 497.449 367.440 ;
      RECT 0.216 368.112 497.449 368.208 ;
      RECT 0.216 368.880 497.449 368.976 ;
      RECT 0.216 369.648 497.449 369.744 ;
      RECT 0.216 370.416 497.449 370.512 ;
      RECT 0.216 371.184 497.449 371.280 ;
      RECT 0.216 371.952 497.449 372.048 ;
      RECT 0.216 372.720 497.449 372.816 ;
      RECT 0.216 373.488 497.449 373.584 ;
      RECT 0.216 374.256 497.449 374.352 ;
      RECT 0.216 375.024 497.449 375.120 ;
      RECT 0.216 375.792 497.449 375.888 ;
      RECT 0.216 376.560 497.449 376.656 ;
      RECT 0.216 377.328 497.449 377.424 ;
      RECT 0.216 378.096 497.449 378.192 ;
      RECT 0.216 378.864 497.449 378.960 ;
      RECT 0.216 379.632 497.449 379.728 ;
      RECT 0.216 380.400 497.449 380.496 ;
      RECT 0.216 381.168 497.449 381.264 ;
      RECT 0.216 381.936 497.449 382.032 ;
      RECT 0.216 382.704 497.449 382.800 ;
      RECT 0.216 383.472 497.449 383.568 ;
      RECT 0.216 384.240 497.449 384.336 ;
      RECT 0.216 385.008 497.449 385.104 ;
      RECT 0.216 385.776 497.449 385.872 ;
      RECT 0.216 386.544 497.449 386.640 ;
      RECT 0.216 387.312 497.449 387.408 ;
      RECT 0.216 388.080 497.449 388.176 ;
      RECT 0.216 388.848 497.449 388.944 ;
      RECT 0.216 389.616 497.449 389.712 ;
      RECT 0.216 390.384 497.449 390.480 ;
      RECT 0.216 391.152 497.449 391.248 ;
      RECT 0.216 391.920 497.449 392.016 ;
      RECT 0.216 392.688 497.449 392.784 ;
      RECT 0.216 393.456 497.449 393.552 ;
      RECT 0.216 394.224 497.449 394.320 ;
      RECT 0.216 394.992 497.449 395.088 ;
      RECT 0.216 395.760 497.449 395.856 ;
      RECT 0.216 396.528 497.449 396.624 ;
      RECT 0.216 397.296 497.449 397.392 ;
      RECT 0.216 398.064 497.449 398.160 ;
      RECT 0.216 398.832 497.449 398.928 ;
      RECT 0.216 399.600 497.449 399.696 ;
      RECT 0.216 400.368 497.449 400.464 ;
      RECT 0.216 401.136 497.449 401.232 ;
      RECT 0.216 401.904 497.449 402.000 ;
      RECT 0.216 402.672 497.449 402.768 ;
      RECT 0.216 403.440 497.449 403.536 ;
      RECT 0.216 404.208 497.449 404.304 ;
      RECT 0.216 404.976 497.449 405.072 ;
      RECT 0.216 405.744 497.449 405.840 ;
      RECT 0.216 406.512 497.449 406.608 ;
      RECT 0.216 407.280 497.449 407.376 ;
      RECT 0.216 408.048 497.449 408.144 ;
      RECT 0.216 408.816 497.449 408.912 ;
      RECT 0.216 409.584 497.449 409.680 ;
      RECT 0.216 410.352 497.449 410.448 ;
      RECT 0.216 411.120 497.449 411.216 ;
      RECT 0.216 411.888 497.449 411.984 ;
      RECT 0.216 412.656 497.449 412.752 ;
      RECT 0.216 413.424 497.449 413.520 ;
      RECT 0.216 414.192 497.449 414.288 ;
      RECT 0.216 414.960 497.449 415.056 ;
      RECT 0.216 415.728 497.449 415.824 ;
      RECT 0.216 416.496 497.449 416.592 ;
      RECT 0.216 417.264 497.449 417.360 ;
      RECT 0.216 418.032 497.449 418.128 ;
      RECT 0.216 418.800 497.449 418.896 ;
      RECT 0.216 419.568 497.449 419.664 ;
      RECT 0.216 420.336 497.449 420.432 ;
      RECT 0.216 421.104 497.449 421.200 ;
      RECT 0.216 421.872 497.449 421.968 ;
      RECT 0.216 422.640 497.449 422.736 ;
      RECT 0.216 423.408 497.449 423.504 ;
      RECT 0.216 424.176 497.449 424.272 ;
      RECT 0.216 424.944 497.449 425.040 ;
      RECT 0.216 425.712 497.449 425.808 ;
      RECT 0.216 426.480 497.449 426.576 ;
      RECT 0.216 427.248 497.449 427.344 ;
      RECT 0.216 428.016 497.449 428.112 ;
      RECT 0.216 428.784 497.449 428.880 ;
      RECT 0.216 429.552 497.449 429.648 ;
      RECT 0.216 430.320 497.449 430.416 ;
      RECT 0.216 431.088 497.449 431.184 ;
      RECT 0.216 431.856 497.449 431.952 ;
      RECT 0.216 432.624 497.449 432.720 ;
      RECT 0.216 433.392 497.449 433.488 ;
      RECT 0.216 434.160 497.449 434.256 ;
      RECT 0.216 434.928 497.449 435.024 ;
      RECT 0.216 435.696 497.449 435.792 ;
      RECT 0.216 436.464 497.449 436.560 ;
      RECT 0.216 437.232 497.449 437.328 ;
      RECT 0.216 438.000 497.449 438.096 ;
      RECT 0.216 438.768 497.449 438.864 ;
      RECT 0.216 439.536 497.449 439.632 ;
      RECT 0.216 440.304 497.449 440.400 ;
      RECT 0.216 441.072 497.449 441.168 ;
      RECT 0.216 441.840 497.449 441.936 ;
      RECT 0.216 442.608 497.449 442.704 ;
      RECT 0.216 443.376 497.449 443.472 ;
      RECT 0.216 444.144 497.449 444.240 ;
      RECT 0.216 444.912 497.449 445.008 ;
      RECT 0.216 445.680 497.449 445.776 ;
      RECT 0.216 446.448 497.449 446.544 ;
      RECT 0.216 447.216 497.449 447.312 ;
      RECT 0.216 447.984 497.449 448.080 ;
      RECT 0.216 448.752 497.449 448.848 ;
      RECT 0.216 449.520 497.449 449.616 ;
      RECT 0.216 450.288 497.449 450.384 ;
      RECT 0.216 451.056 497.449 451.152 ;
      RECT 0.216 451.824 497.449 451.920 ;
      RECT 0.216 452.592 497.449 452.688 ;
      RECT 0.216 453.360 497.449 453.456 ;
      RECT 0.216 454.128 497.449 454.224 ;
      RECT 0.216 454.896 497.449 454.992 ;
      RECT 0.216 455.664 497.449 455.760 ;
      RECT 0.216 456.432 497.449 456.528 ;
      RECT 0.216 457.200 497.449 457.296 ;
      RECT 0.216 457.968 497.449 458.064 ;
      RECT 0.216 458.736 497.449 458.832 ;
      RECT 0.216 459.504 497.449 459.600 ;
      RECT 0.216 460.272 497.449 460.368 ;
      RECT 0.216 461.040 497.449 461.136 ;
      RECT 0.216 461.808 497.449 461.904 ;
      RECT 0.216 462.576 497.449 462.672 ;
      RECT 0.216 463.344 497.449 463.440 ;
      RECT 0.216 464.112 497.449 464.208 ;
      RECT 0.216 464.880 497.449 464.976 ;
      RECT 0.216 465.648 497.449 465.744 ;
      RECT 0.216 466.416 497.449 466.512 ;
      RECT 0.216 467.184 497.449 467.280 ;
      RECT 0.216 467.952 497.449 468.048 ;
      RECT 0.216 468.720 497.449 468.816 ;
      RECT 0.216 469.488 497.449 469.584 ;
      RECT 0.216 470.256 497.449 470.352 ;
      RECT 0.216 471.024 497.449 471.120 ;
      RECT 0.216 471.792 497.449 471.888 ;
      RECT 0.216 472.560 497.449 472.656 ;
      RECT 0.216 473.328 497.449 473.424 ;
      RECT 0.216 474.096 497.449 474.192 ;
      RECT 0.216 474.864 497.449 474.960 ;
      RECT 0.216 475.632 497.449 475.728 ;
      RECT 0.216 476.400 497.449 476.496 ;
      RECT 0.216 477.168 497.449 477.264 ;
      RECT 0.216 477.936 497.449 478.032 ;
      RECT 0.216 478.704 497.449 478.800 ;
      RECT 0.216 479.472 497.449 479.568 ;
      RECT 0.216 480.240 497.449 480.336 ;
      RECT 0.216 481.008 497.449 481.104 ;
      RECT 0.216 481.776 497.449 481.872 ;
      RECT 0.216 482.544 497.449 482.640 ;
      RECT 0.216 483.312 497.449 483.408 ;
      RECT 0.216 484.080 497.449 484.176 ;
      RECT 0.216 484.848 497.449 484.944 ;
      RECT 0.216 485.616 497.449 485.712 ;
      RECT 0.216 486.384 497.449 486.480 ;
      RECT 0.216 487.152 497.449 487.248 ;
      RECT 0.216 487.920 497.449 488.016 ;
      RECT 0.216 488.688 497.449 488.784 ;
      RECT 0.216 489.456 497.449 489.552 ;
      RECT 0.216 490.224 497.449 490.320 ;
      RECT 0.216 490.992 497.449 491.088 ;
      RECT 0.216 491.760 497.449 491.856 ;
      RECT 0.216 492.528 497.449 492.624 ;
      RECT 0.216 493.296 497.449 493.392 ;
      RECT 0.216 494.064 497.449 494.160 ;
      RECT 0.216 494.832 497.449 494.928 ;
      RECT 0.216 495.600 497.449 495.696 ;
      RECT 0.216 496.368 497.449 496.464 ;
      RECT 0.216 497.136 497.449 497.232 ;
      RECT 0.216 497.904 497.449 498.000 ;
      RECT 0.216 498.672 497.449 498.768 ;
      RECT 0.216 499.440 497.449 499.536 ;
      RECT 0.216 500.208 497.449 500.304 ;
      RECT 0.216 500.976 497.449 501.072 ;
      RECT 0.216 501.744 497.449 501.840 ;
      RECT 0.216 502.512 497.449 502.608 ;
      RECT 0.216 503.280 497.449 503.376 ;
      RECT 0.216 504.048 497.449 504.144 ;
      RECT 0.216 504.816 497.449 504.912 ;
      RECT 0.216 505.584 497.449 505.680 ;
      RECT 0.216 506.352 497.449 506.448 ;
      RECT 0.216 507.120 497.449 507.216 ;
      RECT 0.216 507.888 497.449 507.984 ;
      RECT 0.216 508.656 497.449 508.752 ;
      RECT 0.216 509.424 497.449 509.520 ;
      RECT 0.216 510.192 497.449 510.288 ;
      RECT 0.216 510.960 497.449 511.056 ;
      RECT 0.216 511.728 497.449 511.824 ;
      RECT 0.216 512.496 497.449 512.592 ;
      RECT 0.216 513.264 497.449 513.360 ;
      RECT 0.216 514.032 497.449 514.128 ;
      RECT 0.216 514.800 497.449 514.896 ;
      RECT 0.216 515.568 497.449 515.664 ;
      RECT 0.216 516.336 497.449 516.432 ;
      RECT 0.216 517.104 497.449 517.200 ;
      RECT 0.216 517.872 497.449 517.968 ;
      RECT 0.216 518.640 497.449 518.736 ;
      RECT 0.216 519.408 497.449 519.504 ;
      RECT 0.216 520.176 497.449 520.272 ;
      RECT 0.216 520.944 497.449 521.040 ;
      RECT 0.216 521.712 497.449 521.808 ;
      RECT 0.216 522.480 497.449 522.576 ;
      RECT 0.216 523.248 497.449 523.344 ;
      RECT 0.216 524.016 497.449 524.112 ;
      RECT 0.216 524.784 497.449 524.880 ;
      RECT 0.216 525.552 497.449 525.648 ;
      RECT 0.216 526.320 497.449 526.416 ;
      RECT 0.216 527.088 497.449 527.184 ;
      RECT 0.216 527.856 497.449 527.952 ;
      RECT 0.216 528.624 497.449 528.720 ;
      RECT 0.216 529.392 497.449 529.488 ;
      RECT 0.216 530.160 497.449 530.256 ;
      RECT 0.216 530.928 497.449 531.024 ;
      RECT 0.216 531.696 497.449 531.792 ;
      RECT 0.216 532.464 497.449 532.560 ;
      RECT 0.216 533.232 497.449 533.328 ;
      RECT 0.216 534.000 497.449 534.096 ;
      RECT 0.216 534.768 497.449 534.864 ;
      RECT 0.216 535.536 497.449 535.632 ;
      RECT 0.216 536.304 497.449 536.400 ;
      RECT 0.216 537.072 497.449 537.168 ;
      RECT 0.216 537.840 497.449 537.936 ;
      RECT 0.216 538.608 497.449 538.704 ;
      RECT 0.216 539.376 497.449 539.472 ;
      RECT 0.216 540.144 497.449 540.240 ;
      RECT 0.216 540.912 497.449 541.008 ;
      RECT 0.216 541.680 497.449 541.776 ;
      RECT 0.216 542.448 497.449 542.544 ;
      RECT 0.216 543.216 497.449 543.312 ;
      RECT 0.216 543.984 497.449 544.080 ;
      RECT 0.216 544.752 497.449 544.848 ;
      RECT 0.216 545.520 497.449 545.616 ;
      RECT 0.216 546.288 497.449 546.384 ;
      RECT 0.216 547.056 497.449 547.152 ;
      RECT 0.216 547.824 497.449 547.920 ;
      RECT 0.216 548.592 497.449 548.688 ;
      RECT 0.216 549.360 497.449 549.456 ;
      RECT 0.216 550.128 497.449 550.224 ;
      RECT 0.216 550.896 497.449 550.992 ;
      RECT 0.216 551.664 497.449 551.760 ;
      RECT 0.216 552.432 497.449 552.528 ;
      RECT 0.216 553.200 497.449 553.296 ;
      RECT 0.216 553.968 497.449 554.064 ;
      RECT 0.216 554.736 497.449 554.832 ;
      RECT 0.216 555.504 497.449 555.600 ;
      RECT 0.216 556.272 497.449 556.368 ;
      RECT 0.216 557.040 497.449 557.136 ;
      RECT 0.216 557.808 497.449 557.904 ;
      RECT 0.216 558.576 497.449 558.672 ;
      RECT 0.216 559.344 497.449 559.440 ;
      RECT 0.216 560.112 497.449 560.208 ;
      RECT 0.216 560.880 497.449 560.976 ;
      RECT 0.216 561.648 497.449 561.744 ;
      RECT 0.216 562.416 497.449 562.512 ;
      RECT 0.216 563.184 497.449 563.280 ;
      RECT 0.216 563.952 497.449 564.048 ;
      RECT 0.216 564.720 497.449 564.816 ;
      RECT 0.216 565.488 497.449 565.584 ;
      RECT 0.216 566.256 497.449 566.352 ;
      RECT 0.216 567.024 497.449 567.120 ;
      RECT 0.216 567.792 497.449 567.888 ;
      RECT 0.216 568.560 497.449 568.656 ;
      RECT 0.216 569.328 497.449 569.424 ;
      RECT 0.216 570.096 497.449 570.192 ;
      RECT 0.216 570.864 497.449 570.960 ;
      RECT 0.216 571.632 497.449 571.728 ;
      RECT 0.216 572.400 497.449 572.496 ;
      RECT 0.216 573.168 497.449 573.264 ;
      RECT 0.216 573.936 497.449 574.032 ;
      RECT 0.216 574.704 497.449 574.800 ;
      RECT 0.216 575.472 497.449 575.568 ;
      RECT 0.216 576.240 497.449 576.336 ;
      RECT 0.216 577.008 497.449 577.104 ;
      RECT 0.216 577.776 497.449 577.872 ;
      RECT 0.216 578.544 497.449 578.640 ;
      RECT 0.216 579.312 497.449 579.408 ;
      RECT 0.216 580.080 497.449 580.176 ;
      RECT 0.216 580.848 497.449 580.944 ;
      RECT 0.216 581.616 497.449 581.712 ;
      RECT 0.216 582.384 497.449 582.480 ;
      RECT 0.216 583.152 497.449 583.248 ;
      RECT 0.216 583.920 497.449 584.016 ;
      RECT 0.216 584.688 497.449 584.784 ;
      RECT 0.216 585.456 497.449 585.552 ;
      RECT 0.216 586.224 497.449 586.320 ;
      RECT 0.216 586.992 497.449 587.088 ;
      RECT 0.216 587.760 497.449 587.856 ;
      RECT 0.216 588.528 497.449 588.624 ;
      RECT 0.216 589.296 497.449 589.392 ;
      RECT 0.216 590.064 497.449 590.160 ;
      RECT 0.216 590.832 497.449 590.928 ;
      RECT 0.216 591.600 497.449 591.696 ;
      RECT 0.216 592.368 497.449 592.464 ;
      RECT 0.216 593.136 497.449 593.232 ;
      RECT 0.216 593.904 497.449 594.000 ;
      RECT 0.216 594.672 497.449 594.768 ;
      RECT 0.216 595.440 497.449 595.536 ;
      RECT 0.216 596.208 497.449 596.304 ;
      RECT 0.216 596.976 497.449 597.072 ;
      RECT 0.216 597.744 497.449 597.840 ;
      RECT 0.216 598.512 497.449 598.608 ;
      RECT 0.216 599.280 497.449 599.376 ;
      RECT 0.216 600.048 497.449 600.144 ;
      RECT 0.216 600.816 497.449 600.912 ;
      RECT 0.216 601.584 497.449 601.680 ;
      RECT 0.216 602.352 497.449 602.448 ;
      RECT 0.216 603.120 497.449 603.216 ;
      RECT 0.216 603.888 497.449 603.984 ;
      RECT 0.216 604.656 497.449 604.752 ;
      RECT 0.216 605.424 497.449 605.520 ;
      RECT 0.216 606.192 497.449 606.288 ;
      RECT 0.216 606.960 497.449 607.056 ;
      RECT 0.216 607.728 497.449 607.824 ;
      RECT 0.216 608.496 497.449 608.592 ;
      RECT 0.216 609.264 497.449 609.360 ;
      RECT 0.216 610.032 497.449 610.128 ;
      RECT 0.216 610.800 497.449 610.896 ;
      RECT 0.216 611.568 497.449 611.664 ;
      RECT 0.216 612.336 497.449 612.432 ;
      RECT 0.216 613.104 497.449 613.200 ;
      RECT 0.216 613.872 497.449 613.968 ;
      RECT 0.216 614.640 497.449 614.736 ;
      RECT 0.216 615.408 497.449 615.504 ;
      RECT 0.216 616.176 497.449 616.272 ;
      RECT 0.216 616.944 497.449 617.040 ;
      RECT 0.216 617.712 497.449 617.808 ;
      RECT 0.216 618.480 497.449 618.576 ;
      RECT 0.216 619.248 497.449 619.344 ;
      RECT 0.216 620.016 497.449 620.112 ;
      RECT 0.216 620.784 497.449 620.880 ;
      RECT 0.216 621.552 497.449 621.648 ;
    END
  END VSS
  PIN VDD
    DIRECTION INOUT ;
    USE POWER ;
    PORT
      LAYER M4 ;
      RECT 0.216 0.624 497.449 0.720 ;
      RECT 0.216 1.392 497.449 1.488 ;
      RECT 0.216 2.160 497.449 2.256 ;
      RECT 0.216 2.928 497.449 3.024 ;
      RECT 0.216 3.696 497.449 3.792 ;
      RECT 0.216 4.464 497.449 4.560 ;
      RECT 0.216 5.232 497.449 5.328 ;
      RECT 0.216 6.000 497.449 6.096 ;
      RECT 0.216 6.768 497.449 6.864 ;
      RECT 0.216 7.536 497.449 7.632 ;
      RECT 0.216 8.304 497.449 8.400 ;
      RECT 0.216 9.072 497.449 9.168 ;
      RECT 0.216 9.840 497.449 9.936 ;
      RECT 0.216 10.608 497.449 10.704 ;
      RECT 0.216 11.376 497.449 11.472 ;
      RECT 0.216 12.144 497.449 12.240 ;
      RECT 0.216 12.912 497.449 13.008 ;
      RECT 0.216 13.680 497.449 13.776 ;
      RECT 0.216 14.448 497.449 14.544 ;
      RECT 0.216 15.216 497.449 15.312 ;
      RECT 0.216 15.984 497.449 16.080 ;
      RECT 0.216 16.752 497.449 16.848 ;
      RECT 0.216 17.520 497.449 17.616 ;
      RECT 0.216 18.288 497.449 18.384 ;
      RECT 0.216 19.056 497.449 19.152 ;
      RECT 0.216 19.824 497.449 19.920 ;
      RECT 0.216 20.592 497.449 20.688 ;
      RECT 0.216 21.360 497.449 21.456 ;
      RECT 0.216 22.128 497.449 22.224 ;
      RECT 0.216 22.896 497.449 22.992 ;
      RECT 0.216 23.664 497.449 23.760 ;
      RECT 0.216 24.432 497.449 24.528 ;
      RECT 0.216 25.200 497.449 25.296 ;
      RECT 0.216 25.968 497.449 26.064 ;
      RECT 0.216 26.736 497.449 26.832 ;
      RECT 0.216 27.504 497.449 27.600 ;
      RECT 0.216 28.272 497.449 28.368 ;
      RECT 0.216 29.040 497.449 29.136 ;
      RECT 0.216 29.808 497.449 29.904 ;
      RECT 0.216 30.576 497.449 30.672 ;
      RECT 0.216 31.344 497.449 31.440 ;
      RECT 0.216 32.112 497.449 32.208 ;
      RECT 0.216 32.880 497.449 32.976 ;
      RECT 0.216 33.648 497.449 33.744 ;
      RECT 0.216 34.416 497.449 34.512 ;
      RECT 0.216 35.184 497.449 35.280 ;
      RECT 0.216 35.952 497.449 36.048 ;
      RECT 0.216 36.720 497.449 36.816 ;
      RECT 0.216 37.488 497.449 37.584 ;
      RECT 0.216 38.256 497.449 38.352 ;
      RECT 0.216 39.024 497.449 39.120 ;
      RECT 0.216 39.792 497.449 39.888 ;
      RECT 0.216 40.560 497.449 40.656 ;
      RECT 0.216 41.328 497.449 41.424 ;
      RECT 0.216 42.096 497.449 42.192 ;
      RECT 0.216 42.864 497.449 42.960 ;
      RECT 0.216 43.632 497.449 43.728 ;
      RECT 0.216 44.400 497.449 44.496 ;
      RECT 0.216 45.168 497.449 45.264 ;
      RECT 0.216 45.936 497.449 46.032 ;
      RECT 0.216 46.704 497.449 46.800 ;
      RECT 0.216 47.472 497.449 47.568 ;
      RECT 0.216 48.240 497.449 48.336 ;
      RECT 0.216 49.008 497.449 49.104 ;
      RECT 0.216 49.776 497.449 49.872 ;
      RECT 0.216 50.544 497.449 50.640 ;
      RECT 0.216 51.312 497.449 51.408 ;
      RECT 0.216 52.080 497.449 52.176 ;
      RECT 0.216 52.848 497.449 52.944 ;
      RECT 0.216 53.616 497.449 53.712 ;
      RECT 0.216 54.384 497.449 54.480 ;
      RECT 0.216 55.152 497.449 55.248 ;
      RECT 0.216 55.920 497.449 56.016 ;
      RECT 0.216 56.688 497.449 56.784 ;
      RECT 0.216 57.456 497.449 57.552 ;
      RECT 0.216 58.224 497.449 58.320 ;
      RECT 0.216 58.992 497.449 59.088 ;
      RECT 0.216 59.760 497.449 59.856 ;
      RECT 0.216 60.528 497.449 60.624 ;
      RECT 0.216 61.296 497.449 61.392 ;
      RECT 0.216 62.064 497.449 62.160 ;
      RECT 0.216 62.832 497.449 62.928 ;
      RECT 0.216 63.600 497.449 63.696 ;
      RECT 0.216 64.368 497.449 64.464 ;
      RECT 0.216 65.136 497.449 65.232 ;
      RECT 0.216 65.904 497.449 66.000 ;
      RECT 0.216 66.672 497.449 66.768 ;
      RECT 0.216 67.440 497.449 67.536 ;
      RECT 0.216 68.208 497.449 68.304 ;
      RECT 0.216 68.976 497.449 69.072 ;
      RECT 0.216 69.744 497.449 69.840 ;
      RECT 0.216 70.512 497.449 70.608 ;
      RECT 0.216 71.280 497.449 71.376 ;
      RECT 0.216 72.048 497.449 72.144 ;
      RECT 0.216 72.816 497.449 72.912 ;
      RECT 0.216 73.584 497.449 73.680 ;
      RECT 0.216 74.352 497.449 74.448 ;
      RECT 0.216 75.120 497.449 75.216 ;
      RECT 0.216 75.888 497.449 75.984 ;
      RECT 0.216 76.656 497.449 76.752 ;
      RECT 0.216 77.424 497.449 77.520 ;
      RECT 0.216 78.192 497.449 78.288 ;
      RECT 0.216 78.960 497.449 79.056 ;
      RECT 0.216 79.728 497.449 79.824 ;
      RECT 0.216 80.496 497.449 80.592 ;
      RECT 0.216 81.264 497.449 81.360 ;
      RECT 0.216 82.032 497.449 82.128 ;
      RECT 0.216 82.800 497.449 82.896 ;
      RECT 0.216 83.568 497.449 83.664 ;
      RECT 0.216 84.336 497.449 84.432 ;
      RECT 0.216 85.104 497.449 85.200 ;
      RECT 0.216 85.872 497.449 85.968 ;
      RECT 0.216 86.640 497.449 86.736 ;
      RECT 0.216 87.408 497.449 87.504 ;
      RECT 0.216 88.176 497.449 88.272 ;
      RECT 0.216 88.944 497.449 89.040 ;
      RECT 0.216 89.712 497.449 89.808 ;
      RECT 0.216 90.480 497.449 90.576 ;
      RECT 0.216 91.248 497.449 91.344 ;
      RECT 0.216 92.016 497.449 92.112 ;
      RECT 0.216 92.784 497.449 92.880 ;
      RECT 0.216 93.552 497.449 93.648 ;
      RECT 0.216 94.320 497.449 94.416 ;
      RECT 0.216 95.088 497.449 95.184 ;
      RECT 0.216 95.856 497.449 95.952 ;
      RECT 0.216 96.624 497.449 96.720 ;
      RECT 0.216 97.392 497.449 97.488 ;
      RECT 0.216 98.160 497.449 98.256 ;
      RECT 0.216 98.928 497.449 99.024 ;
      RECT 0.216 99.696 497.449 99.792 ;
      RECT 0.216 100.464 497.449 100.560 ;
      RECT 0.216 101.232 497.449 101.328 ;
      RECT 0.216 102.000 497.449 102.096 ;
      RECT 0.216 102.768 497.449 102.864 ;
      RECT 0.216 103.536 497.449 103.632 ;
      RECT 0.216 104.304 497.449 104.400 ;
      RECT 0.216 105.072 497.449 105.168 ;
      RECT 0.216 105.840 497.449 105.936 ;
      RECT 0.216 106.608 497.449 106.704 ;
      RECT 0.216 107.376 497.449 107.472 ;
      RECT 0.216 108.144 497.449 108.240 ;
      RECT 0.216 108.912 497.449 109.008 ;
      RECT 0.216 109.680 497.449 109.776 ;
      RECT 0.216 110.448 497.449 110.544 ;
      RECT 0.216 111.216 497.449 111.312 ;
      RECT 0.216 111.984 497.449 112.080 ;
      RECT 0.216 112.752 497.449 112.848 ;
      RECT 0.216 113.520 497.449 113.616 ;
      RECT 0.216 114.288 497.449 114.384 ;
      RECT 0.216 115.056 497.449 115.152 ;
      RECT 0.216 115.824 497.449 115.920 ;
      RECT 0.216 116.592 497.449 116.688 ;
      RECT 0.216 117.360 497.449 117.456 ;
      RECT 0.216 118.128 497.449 118.224 ;
      RECT 0.216 118.896 497.449 118.992 ;
      RECT 0.216 119.664 497.449 119.760 ;
      RECT 0.216 120.432 497.449 120.528 ;
      RECT 0.216 121.200 497.449 121.296 ;
      RECT 0.216 121.968 497.449 122.064 ;
      RECT 0.216 122.736 497.449 122.832 ;
      RECT 0.216 123.504 497.449 123.600 ;
      RECT 0.216 124.272 497.449 124.368 ;
      RECT 0.216 125.040 497.449 125.136 ;
      RECT 0.216 125.808 497.449 125.904 ;
      RECT 0.216 126.576 497.449 126.672 ;
      RECT 0.216 127.344 497.449 127.440 ;
      RECT 0.216 128.112 497.449 128.208 ;
      RECT 0.216 128.880 497.449 128.976 ;
      RECT 0.216 129.648 497.449 129.744 ;
      RECT 0.216 130.416 497.449 130.512 ;
      RECT 0.216 131.184 497.449 131.280 ;
      RECT 0.216 131.952 497.449 132.048 ;
      RECT 0.216 132.720 497.449 132.816 ;
      RECT 0.216 133.488 497.449 133.584 ;
      RECT 0.216 134.256 497.449 134.352 ;
      RECT 0.216 135.024 497.449 135.120 ;
      RECT 0.216 135.792 497.449 135.888 ;
      RECT 0.216 136.560 497.449 136.656 ;
      RECT 0.216 137.328 497.449 137.424 ;
      RECT 0.216 138.096 497.449 138.192 ;
      RECT 0.216 138.864 497.449 138.960 ;
      RECT 0.216 139.632 497.449 139.728 ;
      RECT 0.216 140.400 497.449 140.496 ;
      RECT 0.216 141.168 497.449 141.264 ;
      RECT 0.216 141.936 497.449 142.032 ;
      RECT 0.216 142.704 497.449 142.800 ;
      RECT 0.216 143.472 497.449 143.568 ;
      RECT 0.216 144.240 497.449 144.336 ;
      RECT 0.216 145.008 497.449 145.104 ;
      RECT 0.216 145.776 497.449 145.872 ;
      RECT 0.216 146.544 497.449 146.640 ;
      RECT 0.216 147.312 497.449 147.408 ;
      RECT 0.216 148.080 497.449 148.176 ;
      RECT 0.216 148.848 497.449 148.944 ;
      RECT 0.216 149.616 497.449 149.712 ;
      RECT 0.216 150.384 497.449 150.480 ;
      RECT 0.216 151.152 497.449 151.248 ;
      RECT 0.216 151.920 497.449 152.016 ;
      RECT 0.216 152.688 497.449 152.784 ;
      RECT 0.216 153.456 497.449 153.552 ;
      RECT 0.216 154.224 497.449 154.320 ;
      RECT 0.216 154.992 497.449 155.088 ;
      RECT 0.216 155.760 497.449 155.856 ;
      RECT 0.216 156.528 497.449 156.624 ;
      RECT 0.216 157.296 497.449 157.392 ;
      RECT 0.216 158.064 497.449 158.160 ;
      RECT 0.216 158.832 497.449 158.928 ;
      RECT 0.216 159.600 497.449 159.696 ;
      RECT 0.216 160.368 497.449 160.464 ;
      RECT 0.216 161.136 497.449 161.232 ;
      RECT 0.216 161.904 497.449 162.000 ;
      RECT 0.216 162.672 497.449 162.768 ;
      RECT 0.216 163.440 497.449 163.536 ;
      RECT 0.216 164.208 497.449 164.304 ;
      RECT 0.216 164.976 497.449 165.072 ;
      RECT 0.216 165.744 497.449 165.840 ;
      RECT 0.216 166.512 497.449 166.608 ;
      RECT 0.216 167.280 497.449 167.376 ;
      RECT 0.216 168.048 497.449 168.144 ;
      RECT 0.216 168.816 497.449 168.912 ;
      RECT 0.216 169.584 497.449 169.680 ;
      RECT 0.216 170.352 497.449 170.448 ;
      RECT 0.216 171.120 497.449 171.216 ;
      RECT 0.216 171.888 497.449 171.984 ;
      RECT 0.216 172.656 497.449 172.752 ;
      RECT 0.216 173.424 497.449 173.520 ;
      RECT 0.216 174.192 497.449 174.288 ;
      RECT 0.216 174.960 497.449 175.056 ;
      RECT 0.216 175.728 497.449 175.824 ;
      RECT 0.216 176.496 497.449 176.592 ;
      RECT 0.216 177.264 497.449 177.360 ;
      RECT 0.216 178.032 497.449 178.128 ;
      RECT 0.216 178.800 497.449 178.896 ;
      RECT 0.216 179.568 497.449 179.664 ;
      RECT 0.216 180.336 497.449 180.432 ;
      RECT 0.216 181.104 497.449 181.200 ;
      RECT 0.216 181.872 497.449 181.968 ;
      RECT 0.216 182.640 497.449 182.736 ;
      RECT 0.216 183.408 497.449 183.504 ;
      RECT 0.216 184.176 497.449 184.272 ;
      RECT 0.216 184.944 497.449 185.040 ;
      RECT 0.216 185.712 497.449 185.808 ;
      RECT 0.216 186.480 497.449 186.576 ;
      RECT 0.216 187.248 497.449 187.344 ;
      RECT 0.216 188.016 497.449 188.112 ;
      RECT 0.216 188.784 497.449 188.880 ;
      RECT 0.216 189.552 497.449 189.648 ;
      RECT 0.216 190.320 497.449 190.416 ;
      RECT 0.216 191.088 497.449 191.184 ;
      RECT 0.216 191.856 497.449 191.952 ;
      RECT 0.216 192.624 497.449 192.720 ;
      RECT 0.216 193.392 497.449 193.488 ;
      RECT 0.216 194.160 497.449 194.256 ;
      RECT 0.216 194.928 497.449 195.024 ;
      RECT 0.216 195.696 497.449 195.792 ;
      RECT 0.216 196.464 497.449 196.560 ;
      RECT 0.216 197.232 497.449 197.328 ;
      RECT 0.216 198.000 497.449 198.096 ;
      RECT 0.216 198.768 497.449 198.864 ;
      RECT 0.216 199.536 497.449 199.632 ;
      RECT 0.216 200.304 497.449 200.400 ;
      RECT 0.216 201.072 497.449 201.168 ;
      RECT 0.216 201.840 497.449 201.936 ;
      RECT 0.216 202.608 497.449 202.704 ;
      RECT 0.216 203.376 497.449 203.472 ;
      RECT 0.216 204.144 497.449 204.240 ;
      RECT 0.216 204.912 497.449 205.008 ;
      RECT 0.216 205.680 497.449 205.776 ;
      RECT 0.216 206.448 497.449 206.544 ;
      RECT 0.216 207.216 497.449 207.312 ;
      RECT 0.216 207.984 497.449 208.080 ;
      RECT 0.216 208.752 497.449 208.848 ;
      RECT 0.216 209.520 497.449 209.616 ;
      RECT 0.216 210.288 497.449 210.384 ;
      RECT 0.216 211.056 497.449 211.152 ;
      RECT 0.216 211.824 497.449 211.920 ;
      RECT 0.216 212.592 497.449 212.688 ;
      RECT 0.216 213.360 497.449 213.456 ;
      RECT 0.216 214.128 497.449 214.224 ;
      RECT 0.216 214.896 497.449 214.992 ;
      RECT 0.216 215.664 497.449 215.760 ;
      RECT 0.216 216.432 497.449 216.528 ;
      RECT 0.216 217.200 497.449 217.296 ;
      RECT 0.216 217.968 497.449 218.064 ;
      RECT 0.216 218.736 497.449 218.832 ;
      RECT 0.216 219.504 497.449 219.600 ;
      RECT 0.216 220.272 497.449 220.368 ;
      RECT 0.216 221.040 497.449 221.136 ;
      RECT 0.216 221.808 497.449 221.904 ;
      RECT 0.216 222.576 497.449 222.672 ;
      RECT 0.216 223.344 497.449 223.440 ;
      RECT 0.216 224.112 497.449 224.208 ;
      RECT 0.216 224.880 497.449 224.976 ;
      RECT 0.216 225.648 497.449 225.744 ;
      RECT 0.216 226.416 497.449 226.512 ;
      RECT 0.216 227.184 497.449 227.280 ;
      RECT 0.216 227.952 497.449 228.048 ;
      RECT 0.216 228.720 497.449 228.816 ;
      RECT 0.216 229.488 497.449 229.584 ;
      RECT 0.216 230.256 497.449 230.352 ;
      RECT 0.216 231.024 497.449 231.120 ;
      RECT 0.216 231.792 497.449 231.888 ;
      RECT 0.216 232.560 497.449 232.656 ;
      RECT 0.216 233.328 497.449 233.424 ;
      RECT 0.216 234.096 497.449 234.192 ;
      RECT 0.216 234.864 497.449 234.960 ;
      RECT 0.216 235.632 497.449 235.728 ;
      RECT 0.216 236.400 497.449 236.496 ;
      RECT 0.216 237.168 497.449 237.264 ;
      RECT 0.216 237.936 497.449 238.032 ;
      RECT 0.216 238.704 497.449 238.800 ;
      RECT 0.216 239.472 497.449 239.568 ;
      RECT 0.216 240.240 497.449 240.336 ;
      RECT 0.216 241.008 497.449 241.104 ;
      RECT 0.216 241.776 497.449 241.872 ;
      RECT 0.216 242.544 497.449 242.640 ;
      RECT 0.216 243.312 497.449 243.408 ;
      RECT 0.216 244.080 497.449 244.176 ;
      RECT 0.216 244.848 497.449 244.944 ;
      RECT 0.216 245.616 497.449 245.712 ;
      RECT 0.216 246.384 497.449 246.480 ;
      RECT 0.216 247.152 497.449 247.248 ;
      RECT 0.216 247.920 497.449 248.016 ;
      RECT 0.216 248.688 497.449 248.784 ;
      RECT 0.216 249.456 497.449 249.552 ;
      RECT 0.216 250.224 497.449 250.320 ;
      RECT 0.216 250.992 497.449 251.088 ;
      RECT 0.216 251.760 497.449 251.856 ;
      RECT 0.216 252.528 497.449 252.624 ;
      RECT 0.216 253.296 497.449 253.392 ;
      RECT 0.216 254.064 497.449 254.160 ;
      RECT 0.216 254.832 497.449 254.928 ;
      RECT 0.216 255.600 497.449 255.696 ;
      RECT 0.216 256.368 497.449 256.464 ;
      RECT 0.216 257.136 497.449 257.232 ;
      RECT 0.216 257.904 497.449 258.000 ;
      RECT 0.216 258.672 497.449 258.768 ;
      RECT 0.216 259.440 497.449 259.536 ;
      RECT 0.216 260.208 497.449 260.304 ;
      RECT 0.216 260.976 497.449 261.072 ;
      RECT 0.216 261.744 497.449 261.840 ;
      RECT 0.216 262.512 497.449 262.608 ;
      RECT 0.216 263.280 497.449 263.376 ;
      RECT 0.216 264.048 497.449 264.144 ;
      RECT 0.216 264.816 497.449 264.912 ;
      RECT 0.216 265.584 497.449 265.680 ;
      RECT 0.216 266.352 497.449 266.448 ;
      RECT 0.216 267.120 497.449 267.216 ;
      RECT 0.216 267.888 497.449 267.984 ;
      RECT 0.216 268.656 497.449 268.752 ;
      RECT 0.216 269.424 497.449 269.520 ;
      RECT 0.216 270.192 497.449 270.288 ;
      RECT 0.216 270.960 497.449 271.056 ;
      RECT 0.216 271.728 497.449 271.824 ;
      RECT 0.216 272.496 497.449 272.592 ;
      RECT 0.216 273.264 497.449 273.360 ;
      RECT 0.216 274.032 497.449 274.128 ;
      RECT 0.216 274.800 497.449 274.896 ;
      RECT 0.216 275.568 497.449 275.664 ;
      RECT 0.216 276.336 497.449 276.432 ;
      RECT 0.216 277.104 497.449 277.200 ;
      RECT 0.216 277.872 497.449 277.968 ;
      RECT 0.216 278.640 497.449 278.736 ;
      RECT 0.216 279.408 497.449 279.504 ;
      RECT 0.216 280.176 497.449 280.272 ;
      RECT 0.216 280.944 497.449 281.040 ;
      RECT 0.216 281.712 497.449 281.808 ;
      RECT 0.216 282.480 497.449 282.576 ;
      RECT 0.216 283.248 497.449 283.344 ;
      RECT 0.216 284.016 497.449 284.112 ;
      RECT 0.216 284.784 497.449 284.880 ;
      RECT 0.216 285.552 497.449 285.648 ;
      RECT 0.216 286.320 497.449 286.416 ;
      RECT 0.216 287.088 497.449 287.184 ;
      RECT 0.216 287.856 497.449 287.952 ;
      RECT 0.216 288.624 497.449 288.720 ;
      RECT 0.216 289.392 497.449 289.488 ;
      RECT 0.216 290.160 497.449 290.256 ;
      RECT 0.216 290.928 497.449 291.024 ;
      RECT 0.216 291.696 497.449 291.792 ;
      RECT 0.216 292.464 497.449 292.560 ;
      RECT 0.216 293.232 497.449 293.328 ;
      RECT 0.216 294.000 497.449 294.096 ;
      RECT 0.216 294.768 497.449 294.864 ;
      RECT 0.216 295.536 497.449 295.632 ;
      RECT 0.216 296.304 497.449 296.400 ;
      RECT 0.216 297.072 497.449 297.168 ;
      RECT 0.216 297.840 497.449 297.936 ;
      RECT 0.216 298.608 497.449 298.704 ;
      RECT 0.216 299.376 497.449 299.472 ;
      RECT 0.216 300.144 497.449 300.240 ;
      RECT 0.216 300.912 497.449 301.008 ;
      RECT 0.216 301.680 497.449 301.776 ;
      RECT 0.216 302.448 497.449 302.544 ;
      RECT 0.216 303.216 497.449 303.312 ;
      RECT 0.216 303.984 497.449 304.080 ;
      RECT 0.216 304.752 497.449 304.848 ;
      RECT 0.216 305.520 497.449 305.616 ;
      RECT 0.216 306.288 497.449 306.384 ;
      RECT 0.216 307.056 497.449 307.152 ;
      RECT 0.216 307.824 497.449 307.920 ;
      RECT 0.216 308.592 497.449 308.688 ;
      RECT 0.216 309.360 497.449 309.456 ;
      RECT 0.216 310.128 497.449 310.224 ;
      RECT 0.216 310.896 497.449 310.992 ;
      RECT 0.216 311.664 497.449 311.760 ;
      RECT 0.216 312.432 497.449 312.528 ;
      RECT 0.216 313.200 497.449 313.296 ;
      RECT 0.216 313.968 497.449 314.064 ;
      RECT 0.216 314.736 497.449 314.832 ;
      RECT 0.216 315.504 497.449 315.600 ;
      RECT 0.216 316.272 497.449 316.368 ;
      RECT 0.216 317.040 497.449 317.136 ;
      RECT 0.216 317.808 497.449 317.904 ;
      RECT 0.216 318.576 497.449 318.672 ;
      RECT 0.216 319.344 497.449 319.440 ;
      RECT 0.216 320.112 497.449 320.208 ;
      RECT 0.216 320.880 497.449 320.976 ;
      RECT 0.216 321.648 497.449 321.744 ;
      RECT 0.216 322.416 497.449 322.512 ;
      RECT 0.216 323.184 497.449 323.280 ;
      RECT 0.216 323.952 497.449 324.048 ;
      RECT 0.216 324.720 497.449 324.816 ;
      RECT 0.216 325.488 497.449 325.584 ;
      RECT 0.216 326.256 497.449 326.352 ;
      RECT 0.216 327.024 497.449 327.120 ;
      RECT 0.216 327.792 497.449 327.888 ;
      RECT 0.216 328.560 497.449 328.656 ;
      RECT 0.216 329.328 497.449 329.424 ;
      RECT 0.216 330.096 497.449 330.192 ;
      RECT 0.216 330.864 497.449 330.960 ;
      RECT 0.216 331.632 497.449 331.728 ;
      RECT 0.216 332.400 497.449 332.496 ;
      RECT 0.216 333.168 497.449 333.264 ;
      RECT 0.216 333.936 497.449 334.032 ;
      RECT 0.216 334.704 497.449 334.800 ;
      RECT 0.216 335.472 497.449 335.568 ;
      RECT 0.216 336.240 497.449 336.336 ;
      RECT 0.216 337.008 497.449 337.104 ;
      RECT 0.216 337.776 497.449 337.872 ;
      RECT 0.216 338.544 497.449 338.640 ;
      RECT 0.216 339.312 497.449 339.408 ;
      RECT 0.216 340.080 497.449 340.176 ;
      RECT 0.216 340.848 497.449 340.944 ;
      RECT 0.216 341.616 497.449 341.712 ;
      RECT 0.216 342.384 497.449 342.480 ;
      RECT 0.216 343.152 497.449 343.248 ;
      RECT 0.216 343.920 497.449 344.016 ;
      RECT 0.216 344.688 497.449 344.784 ;
      RECT 0.216 345.456 497.449 345.552 ;
      RECT 0.216 346.224 497.449 346.320 ;
      RECT 0.216 346.992 497.449 347.088 ;
      RECT 0.216 347.760 497.449 347.856 ;
      RECT 0.216 348.528 497.449 348.624 ;
      RECT 0.216 349.296 497.449 349.392 ;
      RECT 0.216 350.064 497.449 350.160 ;
      RECT 0.216 350.832 497.449 350.928 ;
      RECT 0.216 351.600 497.449 351.696 ;
      RECT 0.216 352.368 497.449 352.464 ;
      RECT 0.216 353.136 497.449 353.232 ;
      RECT 0.216 353.904 497.449 354.000 ;
      RECT 0.216 354.672 497.449 354.768 ;
      RECT 0.216 355.440 497.449 355.536 ;
      RECT 0.216 356.208 497.449 356.304 ;
      RECT 0.216 356.976 497.449 357.072 ;
      RECT 0.216 357.744 497.449 357.840 ;
      RECT 0.216 358.512 497.449 358.608 ;
      RECT 0.216 359.280 497.449 359.376 ;
      RECT 0.216 360.048 497.449 360.144 ;
      RECT 0.216 360.816 497.449 360.912 ;
      RECT 0.216 361.584 497.449 361.680 ;
      RECT 0.216 362.352 497.449 362.448 ;
      RECT 0.216 363.120 497.449 363.216 ;
      RECT 0.216 363.888 497.449 363.984 ;
      RECT 0.216 364.656 497.449 364.752 ;
      RECT 0.216 365.424 497.449 365.520 ;
      RECT 0.216 366.192 497.449 366.288 ;
      RECT 0.216 366.960 497.449 367.056 ;
      RECT 0.216 367.728 497.449 367.824 ;
      RECT 0.216 368.496 497.449 368.592 ;
      RECT 0.216 369.264 497.449 369.360 ;
      RECT 0.216 370.032 497.449 370.128 ;
      RECT 0.216 370.800 497.449 370.896 ;
      RECT 0.216 371.568 497.449 371.664 ;
      RECT 0.216 372.336 497.449 372.432 ;
      RECT 0.216 373.104 497.449 373.200 ;
      RECT 0.216 373.872 497.449 373.968 ;
      RECT 0.216 374.640 497.449 374.736 ;
      RECT 0.216 375.408 497.449 375.504 ;
      RECT 0.216 376.176 497.449 376.272 ;
      RECT 0.216 376.944 497.449 377.040 ;
      RECT 0.216 377.712 497.449 377.808 ;
      RECT 0.216 378.480 497.449 378.576 ;
      RECT 0.216 379.248 497.449 379.344 ;
      RECT 0.216 380.016 497.449 380.112 ;
      RECT 0.216 380.784 497.449 380.880 ;
      RECT 0.216 381.552 497.449 381.648 ;
      RECT 0.216 382.320 497.449 382.416 ;
      RECT 0.216 383.088 497.449 383.184 ;
      RECT 0.216 383.856 497.449 383.952 ;
      RECT 0.216 384.624 497.449 384.720 ;
      RECT 0.216 385.392 497.449 385.488 ;
      RECT 0.216 386.160 497.449 386.256 ;
      RECT 0.216 386.928 497.449 387.024 ;
      RECT 0.216 387.696 497.449 387.792 ;
      RECT 0.216 388.464 497.449 388.560 ;
      RECT 0.216 389.232 497.449 389.328 ;
      RECT 0.216 390.000 497.449 390.096 ;
      RECT 0.216 390.768 497.449 390.864 ;
      RECT 0.216 391.536 497.449 391.632 ;
      RECT 0.216 392.304 497.449 392.400 ;
      RECT 0.216 393.072 497.449 393.168 ;
      RECT 0.216 393.840 497.449 393.936 ;
      RECT 0.216 394.608 497.449 394.704 ;
      RECT 0.216 395.376 497.449 395.472 ;
      RECT 0.216 396.144 497.449 396.240 ;
      RECT 0.216 396.912 497.449 397.008 ;
      RECT 0.216 397.680 497.449 397.776 ;
      RECT 0.216 398.448 497.449 398.544 ;
      RECT 0.216 399.216 497.449 399.312 ;
      RECT 0.216 399.984 497.449 400.080 ;
      RECT 0.216 400.752 497.449 400.848 ;
      RECT 0.216 401.520 497.449 401.616 ;
      RECT 0.216 402.288 497.449 402.384 ;
      RECT 0.216 403.056 497.449 403.152 ;
      RECT 0.216 403.824 497.449 403.920 ;
      RECT 0.216 404.592 497.449 404.688 ;
      RECT 0.216 405.360 497.449 405.456 ;
      RECT 0.216 406.128 497.449 406.224 ;
      RECT 0.216 406.896 497.449 406.992 ;
      RECT 0.216 407.664 497.449 407.760 ;
      RECT 0.216 408.432 497.449 408.528 ;
      RECT 0.216 409.200 497.449 409.296 ;
      RECT 0.216 409.968 497.449 410.064 ;
      RECT 0.216 410.736 497.449 410.832 ;
      RECT 0.216 411.504 497.449 411.600 ;
      RECT 0.216 412.272 497.449 412.368 ;
      RECT 0.216 413.040 497.449 413.136 ;
      RECT 0.216 413.808 497.449 413.904 ;
      RECT 0.216 414.576 497.449 414.672 ;
      RECT 0.216 415.344 497.449 415.440 ;
      RECT 0.216 416.112 497.449 416.208 ;
      RECT 0.216 416.880 497.449 416.976 ;
      RECT 0.216 417.648 497.449 417.744 ;
      RECT 0.216 418.416 497.449 418.512 ;
      RECT 0.216 419.184 497.449 419.280 ;
      RECT 0.216 419.952 497.449 420.048 ;
      RECT 0.216 420.720 497.449 420.816 ;
      RECT 0.216 421.488 497.449 421.584 ;
      RECT 0.216 422.256 497.449 422.352 ;
      RECT 0.216 423.024 497.449 423.120 ;
      RECT 0.216 423.792 497.449 423.888 ;
      RECT 0.216 424.560 497.449 424.656 ;
      RECT 0.216 425.328 497.449 425.424 ;
      RECT 0.216 426.096 497.449 426.192 ;
      RECT 0.216 426.864 497.449 426.960 ;
      RECT 0.216 427.632 497.449 427.728 ;
      RECT 0.216 428.400 497.449 428.496 ;
      RECT 0.216 429.168 497.449 429.264 ;
      RECT 0.216 429.936 497.449 430.032 ;
      RECT 0.216 430.704 497.449 430.800 ;
      RECT 0.216 431.472 497.449 431.568 ;
      RECT 0.216 432.240 497.449 432.336 ;
      RECT 0.216 433.008 497.449 433.104 ;
      RECT 0.216 433.776 497.449 433.872 ;
      RECT 0.216 434.544 497.449 434.640 ;
      RECT 0.216 435.312 497.449 435.408 ;
      RECT 0.216 436.080 497.449 436.176 ;
      RECT 0.216 436.848 497.449 436.944 ;
      RECT 0.216 437.616 497.449 437.712 ;
      RECT 0.216 438.384 497.449 438.480 ;
      RECT 0.216 439.152 497.449 439.248 ;
      RECT 0.216 439.920 497.449 440.016 ;
      RECT 0.216 440.688 497.449 440.784 ;
      RECT 0.216 441.456 497.449 441.552 ;
      RECT 0.216 442.224 497.449 442.320 ;
      RECT 0.216 442.992 497.449 443.088 ;
      RECT 0.216 443.760 497.449 443.856 ;
      RECT 0.216 444.528 497.449 444.624 ;
      RECT 0.216 445.296 497.449 445.392 ;
      RECT 0.216 446.064 497.449 446.160 ;
      RECT 0.216 446.832 497.449 446.928 ;
      RECT 0.216 447.600 497.449 447.696 ;
      RECT 0.216 448.368 497.449 448.464 ;
      RECT 0.216 449.136 497.449 449.232 ;
      RECT 0.216 449.904 497.449 450.000 ;
      RECT 0.216 450.672 497.449 450.768 ;
      RECT 0.216 451.440 497.449 451.536 ;
      RECT 0.216 452.208 497.449 452.304 ;
      RECT 0.216 452.976 497.449 453.072 ;
      RECT 0.216 453.744 497.449 453.840 ;
      RECT 0.216 454.512 497.449 454.608 ;
      RECT 0.216 455.280 497.449 455.376 ;
      RECT 0.216 456.048 497.449 456.144 ;
      RECT 0.216 456.816 497.449 456.912 ;
      RECT 0.216 457.584 497.449 457.680 ;
      RECT 0.216 458.352 497.449 458.448 ;
      RECT 0.216 459.120 497.449 459.216 ;
      RECT 0.216 459.888 497.449 459.984 ;
      RECT 0.216 460.656 497.449 460.752 ;
      RECT 0.216 461.424 497.449 461.520 ;
      RECT 0.216 462.192 497.449 462.288 ;
      RECT 0.216 462.960 497.449 463.056 ;
      RECT 0.216 463.728 497.449 463.824 ;
      RECT 0.216 464.496 497.449 464.592 ;
      RECT 0.216 465.264 497.449 465.360 ;
      RECT 0.216 466.032 497.449 466.128 ;
      RECT 0.216 466.800 497.449 466.896 ;
      RECT 0.216 467.568 497.449 467.664 ;
      RECT 0.216 468.336 497.449 468.432 ;
      RECT 0.216 469.104 497.449 469.200 ;
      RECT 0.216 469.872 497.449 469.968 ;
      RECT 0.216 470.640 497.449 470.736 ;
      RECT 0.216 471.408 497.449 471.504 ;
      RECT 0.216 472.176 497.449 472.272 ;
      RECT 0.216 472.944 497.449 473.040 ;
      RECT 0.216 473.712 497.449 473.808 ;
      RECT 0.216 474.480 497.449 474.576 ;
      RECT 0.216 475.248 497.449 475.344 ;
      RECT 0.216 476.016 497.449 476.112 ;
      RECT 0.216 476.784 497.449 476.880 ;
      RECT 0.216 477.552 497.449 477.648 ;
      RECT 0.216 478.320 497.449 478.416 ;
      RECT 0.216 479.088 497.449 479.184 ;
      RECT 0.216 479.856 497.449 479.952 ;
      RECT 0.216 480.624 497.449 480.720 ;
      RECT 0.216 481.392 497.449 481.488 ;
      RECT 0.216 482.160 497.449 482.256 ;
      RECT 0.216 482.928 497.449 483.024 ;
      RECT 0.216 483.696 497.449 483.792 ;
      RECT 0.216 484.464 497.449 484.560 ;
      RECT 0.216 485.232 497.449 485.328 ;
      RECT 0.216 486.000 497.449 486.096 ;
      RECT 0.216 486.768 497.449 486.864 ;
      RECT 0.216 487.536 497.449 487.632 ;
      RECT 0.216 488.304 497.449 488.400 ;
      RECT 0.216 489.072 497.449 489.168 ;
      RECT 0.216 489.840 497.449 489.936 ;
      RECT 0.216 490.608 497.449 490.704 ;
      RECT 0.216 491.376 497.449 491.472 ;
      RECT 0.216 492.144 497.449 492.240 ;
      RECT 0.216 492.912 497.449 493.008 ;
      RECT 0.216 493.680 497.449 493.776 ;
      RECT 0.216 494.448 497.449 494.544 ;
      RECT 0.216 495.216 497.449 495.312 ;
      RECT 0.216 495.984 497.449 496.080 ;
      RECT 0.216 496.752 497.449 496.848 ;
      RECT 0.216 497.520 497.449 497.616 ;
      RECT 0.216 498.288 497.449 498.384 ;
      RECT 0.216 499.056 497.449 499.152 ;
      RECT 0.216 499.824 497.449 499.920 ;
      RECT 0.216 500.592 497.449 500.688 ;
      RECT 0.216 501.360 497.449 501.456 ;
      RECT 0.216 502.128 497.449 502.224 ;
      RECT 0.216 502.896 497.449 502.992 ;
      RECT 0.216 503.664 497.449 503.760 ;
      RECT 0.216 504.432 497.449 504.528 ;
      RECT 0.216 505.200 497.449 505.296 ;
      RECT 0.216 505.968 497.449 506.064 ;
      RECT 0.216 506.736 497.449 506.832 ;
      RECT 0.216 507.504 497.449 507.600 ;
      RECT 0.216 508.272 497.449 508.368 ;
      RECT 0.216 509.040 497.449 509.136 ;
      RECT 0.216 509.808 497.449 509.904 ;
      RECT 0.216 510.576 497.449 510.672 ;
      RECT 0.216 511.344 497.449 511.440 ;
      RECT 0.216 512.112 497.449 512.208 ;
      RECT 0.216 512.880 497.449 512.976 ;
      RECT 0.216 513.648 497.449 513.744 ;
      RECT 0.216 514.416 497.449 514.512 ;
      RECT 0.216 515.184 497.449 515.280 ;
      RECT 0.216 515.952 497.449 516.048 ;
      RECT 0.216 516.720 497.449 516.816 ;
      RECT 0.216 517.488 497.449 517.584 ;
      RECT 0.216 518.256 497.449 518.352 ;
      RECT 0.216 519.024 497.449 519.120 ;
      RECT 0.216 519.792 497.449 519.888 ;
      RECT 0.216 520.560 497.449 520.656 ;
      RECT 0.216 521.328 497.449 521.424 ;
      RECT 0.216 522.096 497.449 522.192 ;
      RECT 0.216 522.864 497.449 522.960 ;
      RECT 0.216 523.632 497.449 523.728 ;
      RECT 0.216 524.400 497.449 524.496 ;
      RECT 0.216 525.168 497.449 525.264 ;
      RECT 0.216 525.936 497.449 526.032 ;
      RECT 0.216 526.704 497.449 526.800 ;
      RECT 0.216 527.472 497.449 527.568 ;
      RECT 0.216 528.240 497.449 528.336 ;
      RECT 0.216 529.008 497.449 529.104 ;
      RECT 0.216 529.776 497.449 529.872 ;
      RECT 0.216 530.544 497.449 530.640 ;
      RECT 0.216 531.312 497.449 531.408 ;
      RECT 0.216 532.080 497.449 532.176 ;
      RECT 0.216 532.848 497.449 532.944 ;
      RECT 0.216 533.616 497.449 533.712 ;
      RECT 0.216 534.384 497.449 534.480 ;
      RECT 0.216 535.152 497.449 535.248 ;
      RECT 0.216 535.920 497.449 536.016 ;
      RECT 0.216 536.688 497.449 536.784 ;
      RECT 0.216 537.456 497.449 537.552 ;
      RECT 0.216 538.224 497.449 538.320 ;
      RECT 0.216 538.992 497.449 539.088 ;
      RECT 0.216 539.760 497.449 539.856 ;
      RECT 0.216 540.528 497.449 540.624 ;
      RECT 0.216 541.296 497.449 541.392 ;
      RECT 0.216 542.064 497.449 542.160 ;
      RECT 0.216 542.832 497.449 542.928 ;
      RECT 0.216 543.600 497.449 543.696 ;
      RECT 0.216 544.368 497.449 544.464 ;
      RECT 0.216 545.136 497.449 545.232 ;
      RECT 0.216 545.904 497.449 546.000 ;
      RECT 0.216 546.672 497.449 546.768 ;
      RECT 0.216 547.440 497.449 547.536 ;
      RECT 0.216 548.208 497.449 548.304 ;
      RECT 0.216 548.976 497.449 549.072 ;
      RECT 0.216 549.744 497.449 549.840 ;
      RECT 0.216 550.512 497.449 550.608 ;
      RECT 0.216 551.280 497.449 551.376 ;
      RECT 0.216 552.048 497.449 552.144 ;
      RECT 0.216 552.816 497.449 552.912 ;
      RECT 0.216 553.584 497.449 553.680 ;
      RECT 0.216 554.352 497.449 554.448 ;
      RECT 0.216 555.120 497.449 555.216 ;
      RECT 0.216 555.888 497.449 555.984 ;
      RECT 0.216 556.656 497.449 556.752 ;
      RECT 0.216 557.424 497.449 557.520 ;
      RECT 0.216 558.192 497.449 558.288 ;
      RECT 0.216 558.960 497.449 559.056 ;
      RECT 0.216 559.728 497.449 559.824 ;
      RECT 0.216 560.496 497.449 560.592 ;
      RECT 0.216 561.264 497.449 561.360 ;
      RECT 0.216 562.032 497.449 562.128 ;
      RECT 0.216 562.800 497.449 562.896 ;
      RECT 0.216 563.568 497.449 563.664 ;
      RECT 0.216 564.336 497.449 564.432 ;
      RECT 0.216 565.104 497.449 565.200 ;
      RECT 0.216 565.872 497.449 565.968 ;
      RECT 0.216 566.640 497.449 566.736 ;
      RECT 0.216 567.408 497.449 567.504 ;
      RECT 0.216 568.176 497.449 568.272 ;
      RECT 0.216 568.944 497.449 569.040 ;
      RECT 0.216 569.712 497.449 569.808 ;
      RECT 0.216 570.480 497.449 570.576 ;
      RECT 0.216 571.248 497.449 571.344 ;
      RECT 0.216 572.016 497.449 572.112 ;
      RECT 0.216 572.784 497.449 572.880 ;
      RECT 0.216 573.552 497.449 573.648 ;
      RECT 0.216 574.320 497.449 574.416 ;
      RECT 0.216 575.088 497.449 575.184 ;
      RECT 0.216 575.856 497.449 575.952 ;
      RECT 0.216 576.624 497.449 576.720 ;
      RECT 0.216 577.392 497.449 577.488 ;
      RECT 0.216 578.160 497.449 578.256 ;
      RECT 0.216 578.928 497.449 579.024 ;
      RECT 0.216 579.696 497.449 579.792 ;
      RECT 0.216 580.464 497.449 580.560 ;
      RECT 0.216 581.232 497.449 581.328 ;
      RECT 0.216 582.000 497.449 582.096 ;
      RECT 0.216 582.768 497.449 582.864 ;
      RECT 0.216 583.536 497.449 583.632 ;
      RECT 0.216 584.304 497.449 584.400 ;
      RECT 0.216 585.072 497.449 585.168 ;
      RECT 0.216 585.840 497.449 585.936 ;
      RECT 0.216 586.608 497.449 586.704 ;
      RECT 0.216 587.376 497.449 587.472 ;
      RECT 0.216 588.144 497.449 588.240 ;
      RECT 0.216 588.912 497.449 589.008 ;
      RECT 0.216 589.680 497.449 589.776 ;
      RECT 0.216 590.448 497.449 590.544 ;
      RECT 0.216 591.216 497.449 591.312 ;
      RECT 0.216 591.984 497.449 592.080 ;
      RECT 0.216 592.752 497.449 592.848 ;
      RECT 0.216 593.520 497.449 593.616 ;
      RECT 0.216 594.288 497.449 594.384 ;
      RECT 0.216 595.056 497.449 595.152 ;
      RECT 0.216 595.824 497.449 595.920 ;
      RECT 0.216 596.592 497.449 596.688 ;
      RECT 0.216 597.360 497.449 597.456 ;
      RECT 0.216 598.128 497.449 598.224 ;
      RECT 0.216 598.896 497.449 598.992 ;
      RECT 0.216 599.664 497.449 599.760 ;
      RECT 0.216 600.432 497.449 600.528 ;
      RECT 0.216 601.200 497.449 601.296 ;
      RECT 0.216 601.968 497.449 602.064 ;
      RECT 0.216 602.736 497.449 602.832 ;
      RECT 0.216 603.504 497.449 603.600 ;
      RECT 0.216 604.272 497.449 604.368 ;
      RECT 0.216 605.040 497.449 605.136 ;
      RECT 0.216 605.808 497.449 605.904 ;
      RECT 0.216 606.576 497.449 606.672 ;
      RECT 0.216 607.344 497.449 607.440 ;
      RECT 0.216 608.112 497.449 608.208 ;
      RECT 0.216 608.880 497.449 608.976 ;
      RECT 0.216 609.648 497.449 609.744 ;
      RECT 0.216 610.416 497.449 610.512 ;
      RECT 0.216 611.184 497.449 611.280 ;
      RECT 0.216 611.952 497.449 612.048 ;
      RECT 0.216 612.720 497.449 612.816 ;
      RECT 0.216 613.488 497.449 613.584 ;
      RECT 0.216 614.256 497.449 614.352 ;
      RECT 0.216 615.024 497.449 615.120 ;
      RECT 0.216 615.792 497.449 615.888 ;
      RECT 0.216 616.560 497.449 616.656 ;
      RECT 0.216 617.328 497.449 617.424 ;
      RECT 0.216 618.096 497.449 618.192 ;
      RECT 0.216 618.864 497.449 618.960 ;
      RECT 0.216 619.632 497.449 619.728 ;
      RECT 0.216 620.400 497.449 620.496 ;
      RECT 0.216 621.168 497.449 621.264 ;
      RECT 0.216 621.936 497.449 622.032 ;
    END
  END VDD
  OBS
    LAYER M1 ;
    RECT 0 0 497.665 622.080 ;
    LAYER M2 ;
    RECT 0 0 497.665 622.080 ;
    LAYER M3 ;
    RECT 0 0 497.665 622.080 ;
    LAYER M4 ;
    RECT 0 0 497.665 622.080 ;
  END
END fakeram_w16_l32768

END LIBRARY
